VERSION 5.7 ;
BUSBITCHARS "[]" ;
DIVIDERCHAR "/" ;

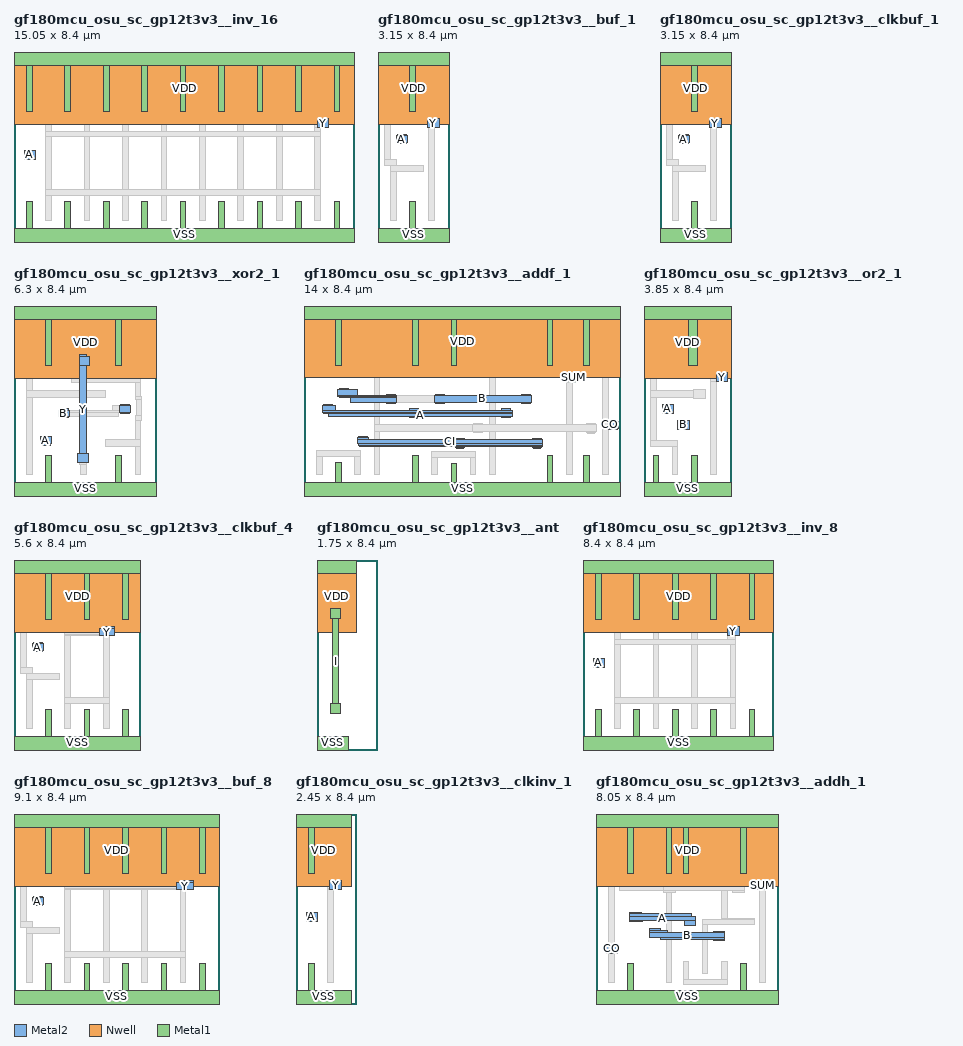
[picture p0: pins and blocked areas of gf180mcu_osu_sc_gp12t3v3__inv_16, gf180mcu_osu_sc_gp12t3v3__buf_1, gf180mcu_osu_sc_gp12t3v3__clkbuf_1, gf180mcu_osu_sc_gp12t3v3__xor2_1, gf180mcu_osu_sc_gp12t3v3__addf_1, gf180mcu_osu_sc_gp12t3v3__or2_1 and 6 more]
MACRO gf180mcu_osu_sc_gp12t3v3__inv_16
  CLASS BLOCK ;
  ORIGIN 0 0 ;
  FOREIGN gf180mcu_osu_sc_gp12t3v3__inv_16 ;
  SIZE 15.050 BY 8.400 ;
  PIN A
    ANTENNAGATEAREA 12.240001 ;
    PORT
      LAYER Metal2 ;
        RECT 0.450 3.650 0.950 4.050 ;
    END
  END A
  PIN Y
    ANTENNADIFFAREA 11.220001 ;
    PORT
      LAYER Metal2 ;
        RECT 13.400 5.050 13.900 5.450 ;
    END
  END Y
  PIN VDD
    ANTENNADIFFAREA 12.295001 ;
    PORT
      LAYER Nwell ;
        RECT 0.000 5.200 15.050 8.400 ;
      LAYER Metal1 ;
        RECT 0.000 7.800 15.050 8.400 ;
        RECT 0.550 5.750 0.800 7.800 ;
        RECT 2.250 5.750 2.500 7.800 ;
        RECT 3.950 5.750 4.200 7.800 ;
        RECT 5.650 5.750 5.900 7.800 ;
        RECT 7.350 5.750 7.600 7.800 ;
        RECT 9.050 5.750 9.300 7.800 ;
        RECT 10.750 5.750 11.000 7.800 ;
        RECT 12.450 5.750 12.700 7.800 ;
        RECT 14.150 5.750 14.400 7.800 ;
    END
  END VDD
  PIN VSS
    ANTENNADIFFAREA 8.172501 ;
    PORT
      LAYER Metal1 ;
        RECT 0.550 0.600 0.800 1.800 ;
        RECT 2.250 0.600 2.500 1.800 ;
        RECT 3.950 0.600 4.200 1.800 ;
        RECT 5.650 0.600 5.900 1.800 ;
        RECT 7.350 0.600 7.600 1.800 ;
        RECT 9.050 0.600 9.300 1.800 ;
        RECT 10.750 0.600 11.000 1.800 ;
        RECT 12.450 0.600 12.700 1.800 ;
        RECT 14.150 0.600 14.400 1.800 ;
        RECT 0.000 0.000 15.050 0.600 ;
    END
  END VSS
  OBS
      LAYER Metal1 ;
        RECT 1.400 4.900 1.650 7.450 ;
        RECT 3.100 4.900 3.350 7.450 ;
        RECT 4.800 4.900 5.050 7.450 ;
        RECT 6.500 4.900 6.750 7.450 ;
        RECT 8.200 4.900 8.450 7.450 ;
        RECT 9.900 4.900 10.150 7.450 ;
        RECT 11.600 4.900 11.850 7.450 ;
        RECT 13.300 5.500 13.550 7.450 ;
        RECT 13.300 5.050 13.900 5.500 ;
        RECT 13.300 4.900 13.550 5.050 ;
        RECT 1.400 4.650 13.550 4.900 ;
        RECT 0.450 3.700 0.950 4.000 ;
        RECT 1.400 2.300 1.650 4.650 ;
        RECT 3.100 2.300 3.350 4.650 ;
        RECT 4.800 2.300 5.050 4.650 ;
        RECT 6.500 2.300 6.750 4.650 ;
        RECT 8.200 2.300 8.450 4.650 ;
        RECT 9.900 2.300 10.150 4.650 ;
        RECT 11.600 2.300 11.850 4.650 ;
        RECT 13.300 2.300 13.550 4.650 ;
        RECT 1.400 2.050 13.550 2.300 ;
        RECT 1.400 0.950 1.650 2.050 ;
        RECT 3.100 0.950 3.350 2.050 ;
        RECT 4.800 0.950 5.050 2.050 ;
        RECT 6.500 0.950 6.750 2.050 ;
        RECT 8.200 0.950 8.450 2.050 ;
        RECT 9.900 0.950 10.150 2.050 ;
        RECT 11.600 0.950 11.850 2.050 ;
        RECT 13.300 0.950 13.550 2.050 ;
      LAYER Via1 ;
        RECT 13.500 5.100 13.800 5.400 ;
        RECT 0.550 3.700 0.850 4.000 ;
  END
END gf180mcu_osu_sc_gp12t3v3__inv_16


MACRO gf180mcu_osu_sc_gp12t3v3__buf_1
  CLASS BLOCK ;
  ORIGIN 0 0 ;
  FOREIGN gf180mcu_osu_sc_gp12t3v3__buf_1 ;
  SIZE 3.150 BY 8.400 ;
  PIN A
    ANTENNAGATEAREA 0.765000 ;
    PORT
      LAYER Metal2 ;
        RECT 0.850 4.700 1.250 4.750 ;
        RECT 0.800 4.400 1.300 4.700 ;
        RECT 0.850 4.350 1.250 4.400 ;
    END
  END A
  PIN Y
    ANTENNADIFFAREA 1.275000 ;
    PORT
      LAYER Metal2 ;
        RECT 2.200 5.050 2.700 5.450 ;
    END
  END Y
  PIN VDD
    ANTENNADIFFAREA 1.610000 ;
    PORT
      LAYER Nwell ;
        RECT 0.000 5.200 3.150 8.400 ;
      LAYER Metal1 ;
        RECT 0.000 7.800 3.150 8.400 ;
        RECT 1.400 5.750 1.650 7.800 ;
    END
  END VDD
  PIN VSS
    ANTENNADIFFAREA 1.142500 ;
    PORT
      LAYER Metal1 ;
        RECT 1.400 0.600 1.650 1.800 ;
        RECT 0.000 0.000 3.150 0.600 ;
    END
  END VSS
  OBS
      LAYER Metal1 ;
        RECT 0.550 5.750 0.800 7.450 ;
        RECT 0.300 5.500 0.800 5.750 ;
        RECT 0.300 3.650 0.550 5.500 ;
        RECT 2.250 5.450 2.500 7.450 ;
        RECT 2.250 5.400 2.550 5.450 ;
        RECT 2.200 5.100 2.700 5.400 ;
        RECT 2.250 5.050 2.550 5.100 ;
        RECT 0.800 4.400 1.300 4.700 ;
        RECT 0.300 3.400 0.800 3.650 ;
        RECT 0.550 3.100 2.000 3.400 ;
        RECT 0.550 0.950 0.800 3.100 ;
        RECT 2.250 0.950 2.500 5.050 ;
      LAYER Via1 ;
        RECT 2.300 5.100 2.600 5.400 ;
        RECT 0.900 4.400 1.200 4.700 ;
  END
END gf180mcu_osu_sc_gp12t3v3__buf_1


MACRO gf180mcu_osu_sc_gp12t3v3__clkbuf_1
  CLASS BLOCK ;
  ORIGIN 0 0 ;
  FOREIGN gf180mcu_osu_sc_gp12t3v3__clkbuf_1 ;
  SIZE 3.150 BY 8.400 ;
  PIN A
    ANTENNAGATEAREA 0.765000 ;
    PORT
      LAYER Metal2 ;
        RECT 0.850 4.700 1.250 4.750 ;
        RECT 0.800 4.400 1.300 4.700 ;
        RECT 0.850 4.350 1.250 4.400 ;
    END
  END A
  PIN Y
    ANTENNADIFFAREA 1.275000 ;
    PORT
      LAYER Metal2 ;
        RECT 2.200 5.050 2.700 5.450 ;
    END
  END Y
  PIN VDD
    ANTENNADIFFAREA 1.610000 ;
    PORT
      LAYER Nwell ;
        RECT 0.000 5.200 3.150 8.400 ;
      LAYER Metal1 ;
        RECT 0.000 7.800 3.150 8.400 ;
        RECT 1.400 5.750 1.650 7.800 ;
    END
  END VDD
  PIN VSS
    ANTENNADIFFAREA 1.142500 ;
    PORT
      LAYER Metal1 ;
        RECT 1.400 0.600 1.650 1.800 ;
        RECT 0.000 0.000 3.150 0.600 ;
    END
  END VSS
  OBS
      LAYER Metal1 ;
        RECT 0.550 6.100 0.800 7.450 ;
        RECT 0.300 5.750 0.800 6.100 ;
        RECT 0.300 3.650 0.550 5.750 ;
        RECT 2.250 5.450 2.500 7.450 ;
        RECT 2.250 5.400 2.550 5.450 ;
        RECT 2.200 5.100 2.700 5.400 ;
        RECT 2.250 5.050 2.550 5.100 ;
        RECT 0.800 4.400 1.300 4.700 ;
        RECT 0.300 3.400 0.800 3.650 ;
        RECT 0.550 3.100 2.000 3.400 ;
        RECT 0.550 0.950 0.800 3.100 ;
        RECT 2.250 0.950 2.500 5.050 ;
      LAYER Via1 ;
        RECT 2.300 5.100 2.600 5.400 ;
        RECT 0.900 4.400 1.200 4.700 ;
  END
END gf180mcu_osu_sc_gp12t3v3__clkbuf_1


MACRO gf180mcu_osu_sc_gp12t3v3__xor2_1
  CLASS BLOCK ;
  ORIGIN 0 0 ;
  FOREIGN gf180mcu_osu_sc_gp12t3v3__xor2_1 ;
  SIZE 6.300 BY 8.400 ;
  PIN A
    ANTENNAGATEAREA 1.530000 ;
    PORT
      LAYER Metal2 ;
        RECT 1.150 2.300 1.650 2.650 ;
        RECT 1.200 2.250 1.600 2.300 ;
    END
  END A
  PIN B
    ANTENNAGATEAREA 1.530000 ;
    PORT
      LAYER Metal2 ;
        RECT 4.700 4.000 5.100 4.050 ;
        RECT 2.000 3.800 2.400 3.850 ;
        RECT 1.950 3.500 2.450 3.800 ;
        RECT 4.650 3.700 5.150 4.000 ;
        RECT 4.700 3.650 5.100 3.700 ;
        RECT 2.000 3.450 2.400 3.500 ;
    END
  END B
  PIN Y
    ANTENNADIFFAREA 2.192500 ;
    PORT
      LAYER Metal2 ;
        RECT 2.900 6.150 3.200 6.250 ;
        RECT 2.900 5.750 3.350 6.150 ;
        RECT 2.900 1.900 3.200 5.750 ;
        RECT 2.800 1.500 3.300 1.900 ;
    END
  END Y
  PIN VDD
    ANTENNADIFFAREA 3.557500 ;
    PORT
      LAYER Nwell ;
        RECT 0.000 5.200 6.300 8.400 ;
      LAYER Metal1 ;
        RECT 0.000 7.800 6.300 8.400 ;
        RECT 1.400 5.750 1.650 7.800 ;
        RECT 4.500 5.750 4.750 7.800 ;
    END
  END VDD
  PIN VSS
    ANTENNADIFFAREA 2.622500 ;
    PORT
      LAYER Metal1 ;
        RECT 1.400 0.600 1.650 1.800 ;
        RECT 4.500 0.600 4.750 1.800 ;
        RECT 0.000 0.000 6.300 0.600 ;
    END
  END VSS
  OBS
      LAYER Metal1 ;
        RECT 0.550 4.650 0.800 7.450 ;
        RECT 2.950 6.250 3.200 7.450 ;
        RECT 2.900 6.150 3.200 6.250 ;
        RECT 2.900 5.750 3.350 6.150 ;
        RECT 2.900 5.650 3.200 5.750 ;
        RECT 5.350 5.300 5.600 7.450 ;
        RECT 2.550 5.000 5.600 5.300 ;
        RECT 0.550 4.350 4.050 4.650 ;
        RECT 5.350 4.400 5.600 5.000 ;
        RECT 0.550 0.950 0.800 4.350 ;
        RECT 5.350 4.250 5.650 4.400 ;
        RECT 4.350 3.800 5.150 4.000 ;
        RECT 1.950 3.700 5.150 3.800 ;
        RECT 1.950 3.500 4.600 3.700 ;
        RECT 5.400 3.550 5.650 4.250 ;
        RECT 5.350 3.350 5.650 3.550 ;
        RECT 1.150 2.300 1.650 2.650 ;
        RECT 5.350 2.500 5.600 3.350 ;
        RECT 4.050 2.200 5.600 2.500 ;
        RECT 2.900 1.400 3.200 1.950 ;
        RECT 2.950 0.950 3.200 1.400 ;
        RECT 5.350 0.950 5.600 2.200 ;
      LAYER Via1 ;
        RECT 3.000 5.800 3.300 6.100 ;
        RECT 2.050 3.500 2.350 3.800 ;
        RECT 4.750 3.700 5.050 4.000 ;
        RECT 1.250 2.300 1.550 2.600 ;
        RECT 2.900 1.550 3.200 1.850 ;
  END
END gf180mcu_osu_sc_gp12t3v3__xor2_1


MACRO gf180mcu_osu_sc_gp12t3v3__addf_1
  CLASS BLOCK ;
  ORIGIN 0 0 ;
  FOREIGN gf180mcu_osu_sc_gp12t3v3__addf_1 ;
  SIZE 14.000 BY 8.400 ;
  PIN A
    ANTENNAGATEAREA 3.060000 ;
    PORT
      LAYER Metal2 ;
        RECT 0.850 4.000 1.250 4.050 ;
        RECT 0.800 3.800 1.400 4.000 ;
        RECT 4.650 3.800 5.050 3.850 ;
        RECT 8.750 3.800 9.150 3.850 ;
        RECT 0.800 3.700 9.200 3.800 ;
        RECT 0.850 3.650 9.200 3.700 ;
        RECT 1.100 3.500 9.200 3.650 ;
        RECT 4.650 3.450 5.050 3.500 ;
        RECT 8.750 3.450 9.150 3.500 ;
    END
  END A
  PIN B
    ANTENNAGATEAREA 3.060000 ;
    PORT
      LAYER Metal2 ;
        RECT 1.550 4.700 1.950 4.750 ;
        RECT 1.500 4.450 2.350 4.700 ;
        RECT 3.650 4.450 4.050 4.500 ;
        RECT 5.800 4.450 6.200 4.500 ;
        RECT 9.600 4.450 10.000 4.500 ;
        RECT 1.500 4.400 4.100 4.450 ;
        RECT 1.550 4.350 4.100 4.400 ;
        RECT 2.050 4.150 4.100 4.350 ;
        RECT 5.750 4.150 10.050 4.450 ;
        RECT 3.650 4.100 4.050 4.150 ;
        RECT 5.800 4.100 6.200 4.150 ;
        RECT 9.600 4.100 10.000 4.150 ;
    END
  END B
  PIN CI
    ANTENNAGATEAREA 2.295000 ;
    PORT
      LAYER Metal2 ;
        RECT 2.400 2.600 2.800 2.650 ;
        RECT 2.350 2.500 2.850 2.600 ;
        RECT 6.700 2.500 7.100 2.550 ;
        RECT 10.100 2.500 10.500 2.550 ;
        RECT 2.350 2.300 10.550 2.500 ;
        RECT 2.400 2.250 10.550 2.300 ;
        RECT 2.450 2.200 10.550 2.250 ;
        RECT 6.700 2.150 7.100 2.200 ;
        RECT 10.100 2.150 10.500 2.200 ;
        RECT 6.750 2.100 7.050 2.150 ;
        RECT 10.150 2.100 10.450 2.150 ;
    END
  END CI
  PIN SUM
    ANTENNADIFFAREA 1.275000 ;
    PORT
      LAYER Metal2 ;
        RECT 11.700 5.400 12.100 5.450 ;
        RECT 11.650 5.100 12.150 5.400 ;
        RECT 11.700 5.050 12.100 5.100 ;
    END
  END SUM
  PIN CO
    ANTENNADIFFAREA 1.275000 ;
    PORT
      LAYER Metal2 ;
        RECT 13.450 3.300 13.850 3.350 ;
        RECT 13.400 3.000 13.900 3.300 ;
        RECT 13.450 2.950 13.850 3.000 ;
    END
  END CO
  PIN VSS
    ANTENNADIFFAREA 6.007501 ;
    PORT
      LAYER Metal1 ;
        RECT 1.400 0.600 1.650 1.500 ;
        RECT 4.800 0.600 5.050 1.800 ;
        RECT 6.500 0.600 6.750 1.450 ;
        RECT 10.750 0.600 11.000 1.800 ;
        RECT 12.350 0.600 12.600 1.800 ;
        RECT 0.000 0.000 14.000 0.600 ;
    END
  END VSS
  PIN VDD
    ANTENNADIFFAREA 8.302501 ;
    PORT
      LAYER Nwell ;
        RECT 0.000 5.250 14.000 8.400 ;
      LAYER Metal1 ;
        RECT 0.000 7.800 14.000 8.400 ;
        RECT 1.400 5.750 1.650 7.800 ;
        RECT 4.800 5.750 5.050 7.800 ;
        RECT 6.500 5.750 6.750 7.800 ;
        RECT 10.750 5.750 11.000 7.800 ;
        RECT 12.350 5.750 12.600 7.800 ;
    END
  END VDD
  OBS
      LAYER Metal1 ;
        RECT 0.550 5.500 0.800 7.450 ;
        RECT 2.250 5.500 2.500 7.450 ;
        RECT 0.550 5.250 2.500 5.500 ;
        RECT 1.500 4.400 2.000 4.700 ;
        RECT 0.800 3.700 1.300 4.000 ;
        RECT 3.100 3.150 3.350 7.450 ;
        RECT 5.650 5.500 5.900 7.450 ;
        RECT 7.350 5.500 7.600 7.450 ;
        RECT 5.650 5.250 7.600 5.500 ;
        RECT 3.600 4.150 6.250 4.450 ;
        RECT 4.600 3.500 5.100 3.800 ;
        RECT 8.200 3.150 8.450 7.450 ;
        RECT 11.600 5.450 11.850 7.450 ;
        RECT 11.600 5.400 12.000 5.450 ;
        RECT 11.600 5.100 12.150 5.400 ;
        RECT 11.600 5.000 12.000 5.100 ;
        RECT 9.550 4.150 10.050 4.450 ;
        RECT 8.700 3.500 9.200 3.800 ;
        RECT 3.100 2.850 7.950 3.150 ;
        RECT 8.200 2.850 11.350 3.150 ;
        RECT 2.350 2.300 2.850 2.600 ;
        RECT 0.550 1.750 2.500 2.000 ;
        RECT 0.550 0.950 0.800 1.750 ;
        RECT 2.250 0.950 2.500 1.750 ;
        RECT 3.100 0.950 3.350 2.850 ;
        RECT 6.650 2.200 7.150 2.500 ;
        RECT 5.650 1.700 7.600 1.950 ;
        RECT 5.650 0.950 5.900 1.700 ;
        RECT 7.350 0.950 7.600 1.700 ;
        RECT 8.200 0.950 8.450 2.850 ;
        RECT 10.050 2.200 10.550 2.500 ;
        RECT 11.600 0.950 11.850 5.000 ;
        RECT 13.200 3.350 13.450 7.450 ;
        RECT 13.200 3.300 13.750 3.350 ;
        RECT 12.450 2.850 12.950 3.150 ;
        RECT 13.200 3.000 13.900 3.300 ;
        RECT 13.200 2.950 13.750 3.000 ;
        RECT 13.200 0.950 13.450 2.950 ;
      LAYER Via1 ;
        RECT 1.600 4.400 1.900 4.700 ;
        RECT 0.900 3.700 1.200 4.000 ;
        RECT 3.700 4.150 4.000 4.450 ;
        RECT 5.850 4.150 6.150 4.450 ;
        RECT 4.700 3.500 5.000 3.800 ;
        RECT 11.750 5.100 12.050 5.400 ;
        RECT 9.650 4.150 9.950 4.450 ;
        RECT 8.800 3.500 9.100 3.800 ;
        RECT 7.550 2.850 7.850 3.150 ;
        RECT 2.450 2.300 2.750 2.600 ;
        RECT 6.750 2.200 7.050 2.500 ;
        RECT 10.150 2.200 10.450 2.500 ;
        RECT 12.550 2.850 12.850 3.150 ;
        RECT 13.500 3.000 13.800 3.300 ;
      LAYER Metal2 ;
        RECT 7.500 3.150 7.900 3.200 ;
        RECT 12.500 3.150 12.900 3.200 ;
        RECT 7.450 2.850 12.950 3.150 ;
        RECT 7.500 2.800 7.900 2.850 ;
        RECT 12.500 2.800 12.900 2.850 ;
        RECT 12.550 2.750 12.850 2.800 ;
  END
END gf180mcu_osu_sc_gp12t3v3__addf_1


MACRO gf180mcu_osu_sc_gp12t3v3__or2_1
  CLASS BLOCK ;
  ORIGIN 0 0 ;
  FOREIGN gf180mcu_osu_sc_gp12t3v3__or2_1 ;
  SIZE 3.850 BY 8.400 ;
  PIN A
    ANTENNAGATEAREA 0.765000 ;
    PORT
      LAYER Metal2 ;
        RECT 0.800 3.650 1.300 4.050 ;
    END
  END A
  PIN B
    ANTENNAGATEAREA 0.765000 ;
    PORT
      LAYER Metal2 ;
        RECT 1.500 2.950 2.000 3.350 ;
    END
  END B
  PIN Y
    ANTENNADIFFAREA 1.275000 ;
    PORT
      LAYER Metal2 ;
        RECT 3.200 5.050 3.700 5.450 ;
    END
  END Y
  PIN VDD
    ANTENNADIFFAREA 2.202500 ;
    PORT
      LAYER Nwell ;
        RECT 0.000 5.200 3.850 8.400 ;
      LAYER Metal1 ;
        RECT 0.000 7.800 3.850 8.400 ;
        RECT 1.950 5.750 2.350 7.800 ;
    END
  END VDD
  PIN VSS
    ANTENNADIFFAREA 1.905000 ;
    PORT
      LAYER Metal1 ;
        RECT 0.400 0.600 0.650 1.800 ;
        RECT 2.100 0.600 2.350 1.800 ;
        RECT 0.000 0.000 3.850 0.600 ;
    END
  END VSS
  OBS
      LAYER Metal1 ;
        RECT 0.550 5.800 0.800 7.450 ;
        RECT 0.300 5.500 0.800 5.800 ;
        RECT 0.300 4.650 0.550 5.500 ;
        RECT 2.950 5.450 3.200 7.450 ;
        RECT 2.950 5.050 3.700 5.450 ;
        RECT 0.300 4.350 2.700 4.650 ;
        RECT 0.300 2.450 0.550 4.350 ;
        RECT 0.800 3.700 1.300 4.000 ;
        RECT 1.500 3.000 2.000 3.300 ;
        RECT 0.300 2.200 1.500 2.450 ;
        RECT 1.250 0.950 1.500 2.200 ;
        RECT 2.950 0.950 3.200 5.050 ;
      LAYER Via1 ;
        RECT 3.300 5.100 3.600 5.400 ;
        RECT 2.300 4.350 2.600 4.650 ;
        RECT 0.900 3.700 1.200 4.000 ;
        RECT 1.600 3.000 1.900 3.300 ;
      LAYER Metal2 ;
        RECT 2.200 4.300 2.700 4.700 ;
  END
END gf180mcu_osu_sc_gp12t3v3__or2_1


MACRO gf180mcu_osu_sc_gp12t3v3__clkbuf_4
  CLASS BLOCK ;
  ORIGIN 0 0 ;
  FOREIGN gf180mcu_osu_sc_gp12t3v3__clkbuf_4 ;
  SIZE 5.600 BY 8.400 ;
  PIN A
    ANTENNAGATEAREA 0.765000 ;
    PORT
      LAYER Metal2 ;
        RECT 0.850 4.700 1.250 4.750 ;
        RECT 0.800 4.400 1.300 4.700 ;
        RECT 0.850 4.350 1.250 4.400 ;
    END
  END A
  PIN Y
    ANTENNADIFFAREA 2.805000 ;
    PORT
      LAYER Metal2 ;
        RECT 3.900 5.350 4.450 5.450 ;
        RECT 3.800 5.050 4.450 5.350 ;
    END
  END Y
  PIN VDD
    ANTENNADIFFAREA 4.070000 ;
    PORT
      LAYER Nwell ;
        RECT 0.000 5.200 5.600 8.400 ;
      LAYER Metal1 ;
        RECT 0.000 7.800 5.600 8.400 ;
        RECT 1.400 5.750 1.650 7.800 ;
        RECT 3.100 5.750 3.350 7.800 ;
        RECT 4.800 5.750 5.050 7.800 ;
    END
  END VDD
  PIN VSS
    ANTENNADIFFAREA 2.710000 ;
    PORT
      LAYER Metal1 ;
        RECT 1.400 0.600 1.650 1.800 ;
        RECT 3.100 0.600 3.350 1.800 ;
        RECT 4.800 0.600 5.050 1.800 ;
        RECT 0.000 0.000 5.600 0.600 ;
    END
  END VSS
  OBS
      LAYER Metal1 ;
        RECT 0.550 6.100 0.800 7.450 ;
        RECT 0.300 5.750 0.800 6.100 ;
        RECT 0.300 3.650 0.550 5.750 ;
        RECT 2.250 5.350 2.500 7.450 ;
        RECT 3.950 5.450 4.200 7.450 ;
        RECT 3.950 5.400 4.300 5.450 ;
        RECT 3.900 5.350 4.450 5.400 ;
        RECT 2.250 5.100 4.450 5.350 ;
        RECT 2.250 5.050 4.300 5.100 ;
        RECT 0.800 4.400 1.300 4.700 ;
        RECT 0.300 3.400 0.800 3.650 ;
        RECT 0.550 3.100 2.000 3.400 ;
        RECT 0.550 0.950 0.800 3.100 ;
        RECT 2.250 2.300 2.500 5.050 ;
        RECT 3.950 2.300 4.200 5.050 ;
        RECT 2.250 2.050 4.200 2.300 ;
        RECT 2.250 0.950 2.500 2.050 ;
        RECT 3.950 0.950 4.200 2.050 ;
      LAYER Via1 ;
        RECT 4.050 5.100 4.350 5.400 ;
        RECT 0.900 4.400 1.200 4.700 ;
  END
END gf180mcu_osu_sc_gp12t3v3__clkbuf_4


MACRO gf180mcu_osu_sc_gp12t3v3__ant
  CLASS BLOCK ;
  ORIGIN 0 0 ;
  FOREIGN gf180mcu_osu_sc_gp12t3v3__ant ;
  SIZE 1.750 BY 8.400 ;
  PIN VDD
    ANTENNADIFFAREA 0.337500 ;
    PORT
      LAYER Nwell ;
        RECT 0.000 5.200 1.750 8.400 ;
      LAYER Metal1 ;
        RECT 0.000 7.800 1.750 8.400 ;
    END
  END VDD
  PIN VSS
    ANTENNADIFFAREA 0.337500 ;
    PORT
      LAYER Metal1 ;
        RECT 0.000 0.000 1.400 0.600 ;
    END
  END VSS
  PIN I
    ANTENNADIFFAREA 0.585000 ;
    PORT
      LAYER Metal1 ;
        RECT 0.600 5.800 1.050 6.250 ;
        RECT 0.700 2.050 0.950 5.800 ;
        RECT 0.600 1.600 1.050 2.050 ;
    END
  END I
END gf180mcu_osu_sc_gp12t3v3__ant


MACRO gf180mcu_osu_sc_gp12t3v3__inv_8
  CLASS BLOCK ;
  ORIGIN 0 0 ;
  FOREIGN gf180mcu_osu_sc_gp12t3v3__inv_8 ;
  SIZE 8.400 BY 8.400 ;
  PIN A
    ANTENNAGATEAREA 6.120000 ;
    PORT
      LAYER Metal2 ;
        RECT 0.450 3.650 0.950 4.050 ;
    END
  END A
  PIN Y
    ANTENNADIFFAREA 5.610001 ;
    PORT
      LAYER Metal2 ;
        RECT 6.400 5.050 6.900 5.450 ;
    END
  END Y
  PIN VDD
    ANTENNADIFFAREA 6.530001 ;
    PORT
      LAYER Nwell ;
        RECT 0.000 5.200 8.400 8.400 ;
      LAYER Metal1 ;
        RECT 0.000 7.800 8.400 8.400 ;
        RECT 0.550 5.750 0.800 7.800 ;
        RECT 2.250 5.750 2.500 7.800 ;
        RECT 3.950 5.750 4.200 7.800 ;
        RECT 5.650 5.750 5.900 7.800 ;
        RECT 7.350 5.750 7.600 7.800 ;
    END
  END VDD
  PIN VSS
    ANTENNADIFFAREA 4.277500 ;
    PORT
      LAYER Metal1 ;
        RECT 0.550 0.600 0.800 1.800 ;
        RECT 2.250 0.600 2.500 1.800 ;
        RECT 3.950 0.600 4.200 1.800 ;
        RECT 5.650 0.600 5.900 1.800 ;
        RECT 7.350 0.600 7.600 1.800 ;
        RECT 0.000 0.000 8.400 0.600 ;
    END
  END VSS
  OBS
      LAYER Metal1 ;
        RECT 1.400 4.900 1.650 7.450 ;
        RECT 3.100 4.900 3.350 7.450 ;
        RECT 4.800 4.900 5.050 7.450 ;
        RECT 6.500 5.450 6.750 7.450 ;
        RECT 6.400 5.050 6.900 5.450 ;
        RECT 6.400 4.900 6.750 5.050 ;
        RECT 1.400 4.650 6.750 4.900 ;
        RECT 0.450 3.700 0.950 4.000 ;
        RECT 1.400 2.300 1.650 4.650 ;
        RECT 3.100 2.300 3.350 4.650 ;
        RECT 4.800 2.300 5.050 4.650 ;
        RECT 6.500 2.300 6.750 4.650 ;
        RECT 1.400 2.050 6.750 2.300 ;
        RECT 1.400 0.950 1.650 2.050 ;
        RECT 3.100 0.950 3.350 2.050 ;
        RECT 4.800 0.950 5.050 2.050 ;
        RECT 6.500 0.950 6.750 2.050 ;
      LAYER Via1 ;
        RECT 6.500 5.100 6.800 5.400 ;
        RECT 0.550 3.700 0.850 4.000 ;
  END
END gf180mcu_osu_sc_gp12t3v3__inv_8


MACRO gf180mcu_osu_sc_gp12t3v3__buf_8
  CLASS BLOCK ;
  ORIGIN 0 0 ;
  FOREIGN gf180mcu_osu_sc_gp12t3v3__buf_8 ;
  SIZE 9.100 BY 8.400 ;
  PIN A
    ANTENNAGATEAREA 0.765000 ;
    PORT
      LAYER Metal2 ;
        RECT 0.850 4.700 1.250 4.750 ;
        RECT 0.800 4.400 1.300 4.700 ;
        RECT 0.850 4.350 1.250 4.400 ;
    END
  END A
  PIN Y
    ANTENNADIFFAREA 5.610001 ;
    PORT
      LAYER Metal2 ;
        RECT 7.450 5.350 7.950 5.450 ;
        RECT 7.200 5.050 7.950 5.350 ;
    END
  END Y
  PIN VDD
    ANTENNADIFFAREA 6.615000 ;
    PORT
      LAYER Nwell ;
        RECT 0.000 5.200 9.100 8.400 ;
      LAYER Metal1 ;
        RECT 0.000 7.800 9.100 8.400 ;
        RECT 1.400 5.750 1.650 7.800 ;
        RECT 3.100 5.750 3.350 7.800 ;
        RECT 4.800 5.750 5.050 7.800 ;
        RECT 6.500 5.750 6.750 7.800 ;
        RECT 8.200 5.750 8.450 7.800 ;
    END
  END VDD
  PIN VSS
    ANTENNADIFFAREA 4.320000 ;
    PORT
      LAYER Metal1 ;
        RECT 1.400 0.600 1.650 1.800 ;
        RECT 3.100 0.600 3.350 1.800 ;
        RECT 4.800 0.600 5.050 1.800 ;
        RECT 6.500 0.600 6.750 1.800 ;
        RECT 8.200 0.600 8.450 1.800 ;
        RECT 0.000 0.000 9.100 0.600 ;
    END
  END VSS
  OBS
      LAYER Metal1 ;
        RECT 0.550 6.100 0.800 7.450 ;
        RECT 0.300 5.750 0.800 6.100 ;
        RECT 0.300 3.650 0.550 5.750 ;
        RECT 2.250 5.350 2.500 7.450 ;
        RECT 3.950 5.350 4.200 7.450 ;
        RECT 5.650 5.350 5.900 7.450 ;
        RECT 7.350 5.450 7.600 7.450 ;
        RECT 7.350 5.400 7.800 5.450 ;
        RECT 7.350 5.350 7.950 5.400 ;
        RECT 2.250 5.100 7.950 5.350 ;
        RECT 2.250 5.050 7.800 5.100 ;
        RECT 0.800 4.400 1.300 4.700 ;
        RECT 0.300 3.400 0.800 3.650 ;
        RECT 0.550 3.100 2.000 3.400 ;
        RECT 0.550 0.950 0.800 3.100 ;
        RECT 2.250 2.300 2.500 5.050 ;
        RECT 3.950 2.300 4.200 5.050 ;
        RECT 5.650 2.300 5.900 5.050 ;
        RECT 7.350 2.300 7.600 5.050 ;
        RECT 2.250 2.050 7.600 2.300 ;
        RECT 2.250 0.950 2.500 2.050 ;
        RECT 3.950 0.950 4.200 2.050 ;
        RECT 5.650 0.950 5.900 2.050 ;
        RECT 7.350 0.950 7.600 2.050 ;
      LAYER Via1 ;
        RECT 7.550 5.100 7.850 5.400 ;
        RECT 0.900 4.400 1.200 4.700 ;
  END
END gf180mcu_osu_sc_gp12t3v3__buf_8


MACRO gf180mcu_osu_sc_gp12t3v3__clkinv_1
  CLASS BLOCK ;
  ORIGIN 0 0 ;
  FOREIGN gf180mcu_osu_sc_gp12t3v3__clkinv_1 ;
  SIZE 2.450 BY 8.400 ;
  PIN A
    ANTENNAGATEAREA 0.765000 ;
    PORT
      LAYER Metal2 ;
        RECT 0.450 3.650 0.950 4.050 ;
    END
  END A
  PIN Y
    ANTENNADIFFAREA 1.275000 ;
    PORT
      LAYER Metal2 ;
        RECT 1.500 5.050 2.000 5.450 ;
    END
  END Y
  PIN VDD
    ANTENNADIFFAREA 1.187500 ;
    PORT
      LAYER Nwell ;
        RECT 0.000 5.200 2.450 8.400 ;
      LAYER Metal1 ;
        RECT 0.000 7.800 2.450 8.400 ;
        RECT 0.550 5.750 0.800 7.800 ;
    END
  END VDD
  PIN VSS
    ANTENNADIFFAREA 0.762500 ;
    PORT
      LAYER Metal1 ;
        RECT 0.550 0.600 0.800 1.800 ;
        RECT 0.000 0.000 2.450 0.600 ;
    END
  END VSS
  OBS
      LAYER Metal1 ;
        RECT 1.400 5.450 1.650 7.450 ;
        RECT 1.400 5.400 1.850 5.450 ;
        RECT 1.400 5.100 2.000 5.400 ;
        RECT 1.400 5.050 1.850 5.100 ;
        RECT 0.450 3.700 0.950 4.000 ;
        RECT 1.400 0.950 1.650 5.050 ;
      LAYER Via1 ;
        RECT 1.600 5.100 1.900 5.400 ;
        RECT 0.550 3.700 0.850 4.000 ;
  END
END gf180mcu_osu_sc_gp12t3v3__clkinv_1


MACRO gf180mcu_osu_sc_gp12t3v3__addh_1
  CLASS BLOCK ;
  ORIGIN 0 0 ;
  FOREIGN gf180mcu_osu_sc_gp12t3v3__addh_1 ;
  SIZE 8.050 BY 8.400 ;
  PIN A
    ANTENNAGATEAREA 1.530000 ;
    PORT
      LAYER Metal2 ;
        RECT 1.500 4.000 2.000 4.050 ;
        RECT 1.500 3.850 4.200 4.000 ;
        RECT 1.500 3.700 4.400 3.850 ;
        RECT 1.500 3.650 2.050 3.700 ;
        RECT 3.900 3.450 4.400 3.700 ;
    END
  END A
  PIN B
    ANTENNAGATEAREA 1.530000 ;
    PORT
      LAYER Metal2 ;
        RECT 2.350 3.250 2.850 3.350 ;
        RECT 2.350 3.150 3.150 3.250 ;
        RECT 5.200 3.150 5.700 3.200 ;
        RECT 2.350 2.950 5.700 3.150 ;
        RECT 2.850 2.850 5.700 2.950 ;
        RECT 5.200 2.800 5.700 2.850 ;
    END
  END B
  PIN SUM
    ANTENNADIFFAREA 1.275000 ;
    PORT
      LAYER Metal2 ;
        RECT 7.100 5.050 7.600 5.450 ;
    END
  END SUM
  PIN CO
    ANTENNADIFFAREA 1.275000 ;
    PORT
      LAYER Metal2 ;
        RECT 0.450 2.250 0.950 2.650 ;
    END
  END CO
  PIN VDD
    ANTENNADIFFAREA 5.595000 ;
    PORT
      LAYER Nwell ;
        RECT 0.000 5.200 8.050 8.400 ;
      LAYER Metal1 ;
        RECT 0.000 7.800 8.050 8.400 ;
        RECT 1.400 5.750 1.650 7.800 ;
        RECT 3.100 5.750 3.350 7.800 ;
        RECT 3.850 5.750 4.100 7.800 ;
        RECT 6.400 5.750 6.650 7.800 ;
    END
  END VDD
  PIN VSS
    ANTENNADIFFAREA 2.960000 ;
    PORT
      LAYER Metal1 ;
        RECT 1.400 0.600 1.650 1.800 ;
        RECT 6.400 0.600 6.650 1.800 ;
        RECT 0.000 0.000 8.050 0.600 ;
    END
  END VSS
  OBS
      LAYER Metal1 ;
        RECT 0.550 2.650 0.800 7.450 ;
        RECT 2.250 5.300 2.500 7.450 ;
        RECT 1.050 5.000 3.500 5.300 ;
        RECT 1.500 3.700 2.000 4.000 ;
        RECT 2.350 3.000 2.850 3.300 ;
        RECT 0.550 2.600 0.850 2.650 ;
        RECT 0.450 2.300 0.950 2.600 ;
        RECT 0.550 2.250 0.850 2.300 ;
        RECT 0.550 0.950 0.800 2.250 ;
        RECT 3.100 0.950 3.350 5.000 ;
        RECT 5.550 3.800 5.800 7.450 ;
        RECT 7.250 5.450 7.500 7.450 ;
        RECT 7.150 5.400 7.500 5.450 ;
        RECT 6.050 5.000 6.550 5.300 ;
        RECT 7.100 5.100 7.600 5.400 ;
        RECT 7.150 5.050 7.500 5.100 ;
        RECT 3.900 3.500 4.400 3.800 ;
        RECT 5.550 3.750 7.000 3.800 ;
        RECT 4.700 3.500 7.000 3.750 ;
        RECT 3.850 1.100 4.100 1.900 ;
        RECT 4.700 1.350 4.950 3.500 ;
        RECT 5.200 2.850 5.700 3.150 ;
        RECT 5.550 1.100 5.800 1.900 ;
        RECT 3.850 0.850 5.800 1.100 ;
        RECT 7.250 0.950 7.500 5.050 ;
      LAYER Via1 ;
        RECT 3.100 5.000 3.400 5.300 ;
        RECT 1.600 3.700 1.900 4.000 ;
        RECT 2.450 3.000 2.750 3.300 ;
        RECT 0.550 2.300 0.850 2.600 ;
        RECT 6.150 5.000 6.450 5.300 ;
        RECT 7.200 5.100 7.500 5.400 ;
        RECT 4.000 3.500 4.300 3.800 ;
        RECT 5.300 2.850 5.600 3.150 ;
      LAYER Metal2 ;
        RECT 3.000 5.300 3.500 5.350 ;
        RECT 6.050 5.300 6.550 5.350 ;
        RECT 3.000 5.000 6.550 5.300 ;
        RECT 3.000 4.950 3.500 5.000 ;
        RECT 6.050 4.950 6.550 5.000 ;
  END
END gf180mcu_osu_sc_gp12t3v3__addh_1


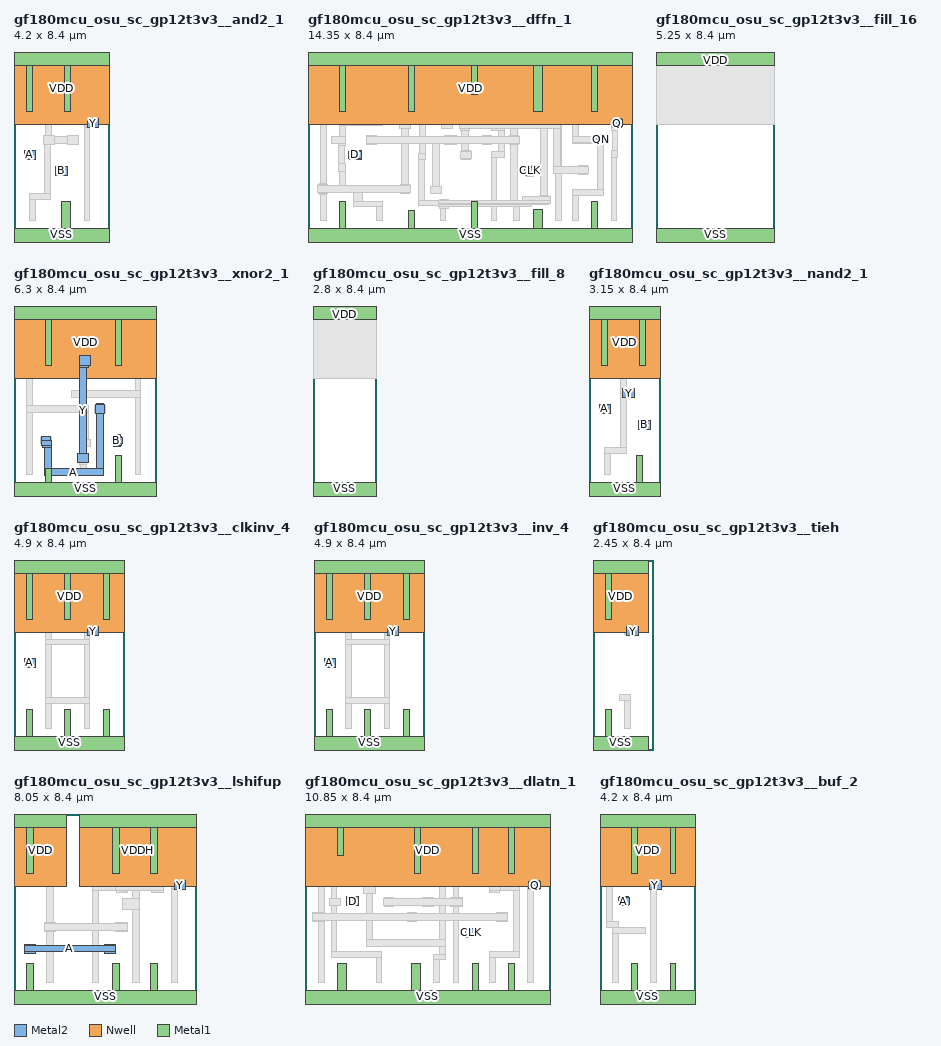
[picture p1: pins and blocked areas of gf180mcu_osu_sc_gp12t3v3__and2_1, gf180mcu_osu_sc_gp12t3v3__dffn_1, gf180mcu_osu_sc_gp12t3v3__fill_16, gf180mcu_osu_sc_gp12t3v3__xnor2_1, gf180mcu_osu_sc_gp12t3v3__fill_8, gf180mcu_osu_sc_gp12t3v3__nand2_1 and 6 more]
MACRO gf180mcu_osu_sc_gp12t3v3__and2_1
  CLASS BLOCK ;
  ORIGIN 0 0 ;
  FOREIGN gf180mcu_osu_sc_gp12t3v3__and2_1 ;
  SIZE 4.200 BY 8.400 ;
  PIN A
    ANTENNAGATEAREA 0.765000 ;
    PORT
      LAYER Metal2 ;
        RECT 0.450 3.650 0.950 4.050 ;
    END
  END A
  PIN B
    ANTENNAGATEAREA 0.765000 ;
    PORT
      LAYER Metal2 ;
        RECT 1.850 2.950 2.350 3.350 ;
    END
  END B
  PIN Y
    ANTENNADIFFAREA 1.275000 ;
    PORT
      LAYER Metal2 ;
        RECT 3.250 5.050 3.750 5.450 ;
    END
  END Y
  PIN VDD
    ANTENNADIFFAREA 2.797500 ;
    PORT
      LAYER Nwell ;
        RECT 0.000 5.200 4.200 8.400 ;
      LAYER Metal1 ;
        RECT 0.000 7.800 4.200 8.400 ;
        RECT 0.550 5.750 0.800 7.800 ;
        RECT 2.250 5.750 2.500 7.800 ;
    END
  END VDD
  PIN VSS
    ANTENNADIFFAREA 1.607500 ;
    PORT
      LAYER Metal1 ;
        RECT 2.100 0.600 2.500 1.800 ;
        RECT 0.000 0.000 4.200 0.600 ;
    END
  END VSS
  OBS
      LAYER Metal1 ;
        RECT 1.400 4.650 1.650 7.450 ;
        RECT 3.100 5.450 3.350 7.450 ;
        RECT 3.100 5.400 3.600 5.450 ;
        RECT 3.100 5.100 3.750 5.400 ;
        RECT 3.100 5.050 3.650 5.100 ;
        RECT 1.300 4.350 2.850 4.650 ;
        RECT 0.450 3.700 0.950 4.000 ;
        RECT 1.350 2.150 1.600 4.350 ;
        RECT 1.850 3.000 2.350 3.300 ;
        RECT 0.700 1.900 1.600 2.150 ;
        RECT 0.700 0.950 0.950 1.900 ;
        RECT 3.100 0.950 3.350 5.050 ;
      LAYER Via1 ;
        RECT 3.350 5.100 3.650 5.400 ;
        RECT 1.400 4.350 1.700 4.650 ;
        RECT 2.450 4.350 2.750 4.650 ;
        RECT 0.550 3.700 0.850 4.000 ;
        RECT 1.950 3.000 2.250 3.300 ;
      LAYER Metal2 ;
        RECT 1.300 4.300 1.800 4.700 ;
        RECT 2.350 4.300 2.850 4.700 ;
  END
END gf180mcu_osu_sc_gp12t3v3__and2_1


MACRO gf180mcu_osu_sc_gp12t3v3__dffn_1
  CLASS BLOCK ;
  ORIGIN 0 0 ;
  FOREIGN gf180mcu_osu_sc_gp12t3v3__dffn_1 ;
  SIZE 14.350 BY 8.400 ;
  PIN D
    ANTENNAGATEAREA 0.765000 ;
    PORT
      LAYER Metal2 ;
        RECT 1.850 4.000 2.350 4.050 ;
        RECT 1.800 3.700 2.350 4.000 ;
        RECT 1.850 3.650 2.350 3.700 ;
    END
  END D
  PIN CLK
    ANTENNAGATEAREA 0.765000 ;
    PORT
      LAYER Metal2 ;
        RECT 9.600 3.300 10.000 3.350 ;
        RECT 9.550 3.000 10.050 3.300 ;
        RECT 9.600 2.950 10.000 3.000 ;
    END
  END CLK
  PIN Q
    ANTENNADIFFAREA 1.275000 ;
    PORT
      LAYER Metal2 ;
        RECT 13.450 5.400 13.850 5.450 ;
        RECT 13.400 5.100 13.900 5.400 ;
        RECT 13.450 5.050 13.850 5.100 ;
    END
  END Q
  PIN QN
    ANTENNAGATEAREA 0.765000 ;
    ANTENNADIFFAREA 1.275000 ;
    PORT
      LAYER Metal2 ;
        RECT 12.750 4.700 13.150 4.750 ;
        RECT 12.700 4.400 13.200 4.700 ;
        RECT 12.750 4.350 13.150 4.400 ;
    END
  END QN
  PIN VDD
    ANTENNADIFFAREA 8.642501 ;
    PORT
      LAYER Nwell ;
        RECT 0.000 5.200 14.350 8.400 ;
      LAYER Metal1 ;
        RECT 0.000 7.800 14.350 8.400 ;
        RECT 1.400 5.750 1.650 7.800 ;
        RECT 4.450 5.750 4.700 7.800 ;
        RECT 7.250 6.500 7.500 7.800 ;
        RECT 9.950 5.750 10.350 7.800 ;
        RECT 12.550 5.750 12.800 7.800 ;
    END
  END VDD
  PIN VSS
    ANTENNADIFFAREA 6.102500 ;
    PORT
      LAYER Metal1 ;
        RECT 1.400 0.600 1.650 1.800 ;
        RECT 4.450 0.600 4.700 1.400 ;
        RECT 7.250 0.600 7.500 1.800 ;
        RECT 9.950 0.600 10.350 1.450 ;
        RECT 12.550 0.600 12.800 1.800 ;
        RECT 0.000 0.000 14.350 0.600 ;
    END
  END VSS
  OBS
      LAYER Metal1 ;
        RECT 0.550 2.600 0.800 7.450 ;
        RECT 3.050 5.400 3.300 7.450 ;
        RECT 5.850 6.500 6.100 7.450 ;
        RECT 1.400 5.150 3.300 5.400 ;
        RECT 4.950 6.250 6.100 6.500 ;
        RECT 8.100 6.250 8.350 7.450 ;
        RECT 1.400 4.650 1.650 5.150 ;
        RECT 4.050 5.000 4.550 5.300 ;
        RECT 1.050 4.350 1.650 4.650 ;
        RECT 2.600 4.350 3.100 4.650 ;
        RECT 1.350 4.250 1.650 4.350 ;
        RECT 2.700 4.300 3.000 4.350 ;
        RECT 1.350 3.450 1.600 4.250 ;
        RECT 1.850 3.700 2.350 4.000 ;
        RECT 1.350 3.100 1.650 3.450 ;
        RECT 0.500 2.100 0.800 2.600 ;
        RECT 1.400 2.500 1.650 3.100 ;
        RECT 4.150 2.500 4.450 5.000 ;
        RECT 4.950 3.900 5.200 6.250 ;
        RECT 8.100 5.950 8.400 6.250 ;
        RECT 9.100 6.000 9.350 7.450 ;
        RECT 6.000 5.750 8.400 5.950 ;
        RECT 8.950 5.750 9.350 6.000 ;
        RECT 6.000 5.650 8.350 5.750 ;
        RECT 6.000 5.300 6.300 5.650 ;
        RECT 5.900 5.000 6.400 5.300 ;
        RECT 6.700 5.000 7.200 5.300 ;
        RECT 8.100 5.200 8.350 5.650 ;
        RECT 4.900 3.650 5.200 3.900 ;
        RECT 5.500 4.350 6.550 4.650 ;
        RECT 1.400 2.250 2.400 2.500 ;
        RECT 0.550 0.950 0.800 2.100 ;
        RECT 2.000 1.800 2.400 2.250 ;
        RECT 4.050 2.200 4.550 2.500 ;
        RECT 4.900 1.850 5.150 3.650 ;
        RECT 5.500 2.450 5.800 4.350 ;
        RECT 6.800 4.000 7.100 5.000 ;
        RECT 8.100 4.950 8.700 5.200 ;
        RECT 7.650 4.350 8.150 4.650 ;
        RECT 8.400 4.000 8.700 4.950 ;
        RECT 6.750 3.700 7.250 4.000 ;
        RECT 8.100 3.750 8.700 4.000 ;
        RECT 5.400 2.150 5.900 2.450 ;
        RECT 2.000 1.550 3.300 1.800 ;
        RECT 4.900 1.600 6.250 1.850 ;
        RECT 3.050 0.950 3.300 1.550 ;
        RECT 5.850 1.550 6.250 1.600 ;
        RECT 5.850 0.950 6.100 1.550 ;
        RECT 8.100 0.950 8.350 3.750 ;
        RECT 8.950 1.850 9.250 5.750 ;
        RECT 10.300 5.300 10.600 5.400 ;
        RECT 10.200 5.000 10.700 5.300 ;
        RECT 9.650 3.300 9.950 3.400 ;
        RECT 9.550 3.000 10.050 3.300 ;
        RECT 9.650 2.900 9.950 3.000 ;
        RECT 10.300 2.000 10.600 5.000 ;
        RECT 10.950 3.350 11.200 7.450 ;
        RECT 11.700 4.650 11.950 7.450 ;
        RECT 13.400 5.450 13.650 7.450 ;
        RECT 13.400 5.100 13.900 5.450 ;
        RECT 13.400 5.050 13.850 5.100 ;
        RECT 13.400 4.950 13.700 5.050 ;
        RECT 12.700 4.650 13.200 4.700 ;
        RECT 11.700 4.400 13.200 4.650 ;
        RECT 11.700 4.350 13.100 4.400 ;
        RECT 12.800 4.300 13.100 4.350 ;
        RECT 10.950 3.050 12.400 3.350 ;
        RECT 8.950 1.600 9.350 1.850 ;
        RECT 10.200 1.700 10.700 2.000 ;
        RECT 9.100 0.950 9.350 1.600 ;
        RECT 10.950 0.950 11.200 3.050 ;
        RECT 12.800 2.300 13.050 4.300 ;
        RECT 13.450 4.050 13.700 4.950 ;
        RECT 11.700 2.050 13.050 2.300 ;
        RECT 13.400 3.750 13.700 4.050 ;
        RECT 11.700 0.950 11.950 2.050 ;
        RECT 13.400 0.950 13.650 3.750 ;
      LAYER Via1 ;
        RECT 2.700 4.350 3.000 4.650 ;
        RECT 1.950 3.700 2.250 4.000 ;
        RECT 0.500 2.200 0.800 2.500 ;
        RECT 6.800 5.000 7.100 5.300 ;
        RECT 6.150 4.350 6.450 4.650 ;
        RECT 4.150 2.200 4.450 2.500 ;
        RECT 7.750 4.350 8.050 4.650 ;
        RECT 6.850 3.700 7.150 4.000 ;
        RECT 8.950 4.350 9.250 4.650 ;
        RECT 9.650 3.000 9.950 3.300 ;
        RECT 13.500 5.100 13.800 5.400 ;
        RECT 12.800 4.400 13.100 4.700 ;
        RECT 12.000 3.050 12.300 3.350 ;
        RECT 10.300 1.700 10.600 2.000 ;
      LAYER Metal2 ;
        RECT 6.750 5.300 7.150 5.350 ;
        RECT 6.700 5.000 11.150 5.300 ;
        RECT 6.750 4.950 7.150 5.000 ;
        RECT 2.600 4.650 3.050 4.700 ;
        RECT 6.050 4.650 6.550 4.700 ;
        RECT 7.700 4.650 8.100 4.700 ;
        RECT 8.900 4.650 9.300 4.700 ;
        RECT 2.600 4.350 9.350 4.650 ;
        RECT 2.600 4.300 3.050 4.350 ;
        RECT 6.050 4.300 6.550 4.350 ;
        RECT 7.700 4.300 8.100 4.350 ;
        RECT 8.900 4.300 9.300 4.350 ;
        RECT 6.800 4.000 7.200 4.050 ;
        RECT 6.750 3.700 7.250 4.000 ;
        RECT 6.800 3.650 7.200 3.700 ;
        RECT 10.850 3.350 11.150 5.000 ;
        RECT 11.950 3.350 12.350 3.400 ;
        RECT 10.850 3.050 12.400 3.350 ;
        RECT 11.950 3.000 12.350 3.050 ;
        RECT 0.450 2.500 0.850 2.550 ;
        RECT 4.100 2.500 4.500 2.550 ;
        RECT 0.400 2.200 4.550 2.500 ;
        RECT 0.450 2.150 0.850 2.200 ;
        RECT 4.100 2.150 4.500 2.200 ;
        RECT 10.250 2.000 10.650 2.050 ;
        RECT 5.800 1.850 6.200 1.900 ;
        RECT 9.500 1.850 10.700 2.000 ;
        RECT 5.750 1.700 10.700 1.850 ;
        RECT 5.750 1.650 10.650 1.700 ;
        RECT 5.750 1.550 9.900 1.650 ;
        RECT 5.800 1.500 6.200 1.550 ;
  END
END gf180mcu_osu_sc_gp12t3v3__dffn_1


MACRO gf180mcu_osu_sc_gp12t3v3__fill_16
  CLASS BLOCK ;
  ORIGIN 0 0 ;
  FOREIGN gf180mcu_osu_sc_gp12t3v3__fill_16 ;
  SIZE 5.250 BY 8.400 ;
  PIN VDD
    PORT
      LAYER Metal1 ;
        RECT 0.000 7.800 5.250 8.400 ;
    END
  END VDD
  PIN VSS
    PORT
      LAYER Metal1 ;
        RECT 0.000 0.000 5.250 0.600 ;
    END
  END VSS
  OBS
      LAYER Nwell ;
        RECT 0.000 5.200 5.250 8.400 ;
  END
END gf180mcu_osu_sc_gp12t3v3__fill_16


MACRO gf180mcu_osu_sc_gp12t3v3__xnor2_1
  CLASS BLOCK ;
  ORIGIN 0 0 ;
  FOREIGN gf180mcu_osu_sc_gp12t3v3__xnor2_1 ;
  SIZE 6.300 BY 8.400 ;
  PIN A
    ANTENNAGATEAREA 1.530000 ;
    PORT
      LAYER Metal2 ;
        RECT 3.650 4.050 3.950 4.100 ;
        RECT 3.600 3.650 4.000 4.050 ;
        RECT 1.200 2.450 1.600 2.650 ;
        RECT 1.200 2.250 1.650 2.450 ;
        RECT 1.250 2.150 1.650 2.250 ;
        RECT 1.350 1.200 1.650 2.150 ;
        RECT 3.650 1.200 3.950 3.650 ;
        RECT 1.350 0.900 3.950 1.200 ;
    END
  END A
  PIN B
    ANTENNAGATEAREA 1.530000 ;
    PORT
      LAYER Metal2 ;
        RECT 4.400 2.650 4.700 2.700 ;
        RECT 4.350 2.600 4.750 2.650 ;
        RECT 4.300 2.300 4.800 2.600 ;
        RECT 4.350 2.250 4.750 2.300 ;
        RECT 4.400 2.200 4.700 2.250 ;
    END
  END B
  PIN Y
    ANTENNADIFFAREA 2.175000 ;
    PORT
      LAYER Metal2 ;
        RECT 2.900 5.750 3.400 6.200 ;
        RECT 2.900 5.700 3.300 5.750 ;
        RECT 2.900 1.900 3.200 5.700 ;
        RECT 2.800 1.500 3.300 1.900 ;
    END
  END Y
  PIN VDD
    ANTENNADIFFAREA 3.557500 ;
    PORT
      LAYER Nwell ;
        RECT 0.000 5.200 6.300 8.400 ;
      LAYER Metal1 ;
        RECT 0.000 7.800 6.300 8.400 ;
        RECT 1.400 5.750 1.650 7.800 ;
        RECT 4.500 5.750 4.750 7.800 ;
    END
  END VDD
  PIN VSS
    ANTENNADIFFAREA 2.622500 ;
    PORT
      LAYER Metal1 ;
        RECT 1.400 0.600 1.650 1.800 ;
        RECT 4.500 0.600 4.750 1.800 ;
        RECT 0.000 0.000 6.300 0.600 ;
    END
  END VSS
  OBS
      LAYER Metal1 ;
        RECT 0.550 4.000 0.800 7.450 ;
        RECT 2.950 6.200 3.200 7.450 ;
        RECT 2.900 5.700 3.300 6.200 ;
        RECT 2.900 5.600 3.200 5.700 ;
        RECT 5.350 4.650 5.600 7.450 ;
        RECT 2.550 4.350 5.600 4.650 ;
        RECT 0.550 3.700 3.300 4.000 ;
        RECT 3.550 3.700 4.050 4.000 ;
        RECT 0.550 0.950 0.800 3.700 ;
        RECT 1.150 2.300 1.650 2.600 ;
        RECT 3.000 2.500 3.300 3.700 ;
        RECT 2.900 2.200 3.400 2.500 ;
        RECT 4.300 2.300 4.800 2.600 ;
        RECT 2.900 1.400 3.200 1.950 ;
        RECT 2.950 0.950 3.200 1.400 ;
        RECT 5.350 0.950 5.600 4.350 ;
      LAYER Via1 ;
        RECT 3.000 5.800 3.300 6.100 ;
        RECT 3.650 3.700 3.950 4.000 ;
        RECT 1.250 2.300 1.550 2.600 ;
        RECT 4.400 2.300 4.700 2.600 ;
        RECT 2.900 1.550 3.200 1.850 ;
  END
END gf180mcu_osu_sc_gp12t3v3__xnor2_1


MACRO gf180mcu_osu_sc_gp12t3v3__fill_8
  CLASS BLOCK ;
  ORIGIN 0 0 ;
  FOREIGN gf180mcu_osu_sc_gp12t3v3__fill_8 ;
  SIZE 2.800 BY 8.400 ;
  PIN VDD
    PORT
      LAYER Metal1 ;
        RECT 0.000 7.800 2.800 8.400 ;
    END
  END VDD
  PIN VSS
    PORT
      LAYER Metal1 ;
        RECT 0.000 0.000 2.800 0.600 ;
    END
  END VSS
  OBS
      LAYER Nwell ;
        RECT 0.000 5.200 2.800 8.400 ;
  END
END gf180mcu_osu_sc_gp12t3v3__fill_8


MACRO gf180mcu_osu_sc_gp12t3v3__nand2_1
  CLASS BLOCK ;
  ORIGIN 0 0 ;
  FOREIGN gf180mcu_osu_sc_gp12t3v3__nand2_1 ;
  SIZE 3.150 BY 8.400 ;
  PIN A
    ANTENNAGATEAREA 0.765000 ;
    PORT
      LAYER Metal2 ;
        RECT 0.450 3.650 0.950 4.050 ;
    END
  END A
  PIN B
    ANTENNAGATEAREA 0.765000 ;
    PORT
      LAYER Metal2 ;
        RECT 2.200 2.950 2.700 3.350 ;
    END
  END B
  PIN Y
    ANTENNADIFFAREA 1.360000 ;
    PORT
      LAYER Metal2 ;
        RECT 1.500 4.350 2.000 4.750 ;
    END
  END Y
  PIN VDD
    ANTENNADIFFAREA 2.375000 ;
    PORT
      LAYER Nwell ;
        RECT 0.000 5.200 3.150 8.400 ;
      LAYER Metal1 ;
        RECT 0.000 7.800 3.150 8.400 ;
        RECT 0.550 5.750 0.800 7.800 ;
        RECT 2.250 5.750 2.500 7.800 ;
    END
  END VDD
  PIN VSS
    ANTENNADIFFAREA 1.100000 ;
    PORT
      LAYER Metal1 ;
        RECT 2.100 0.600 2.350 1.800 ;
        RECT 0.000 0.000 3.150 0.600 ;
    END
  END VSS
  OBS
      LAYER Metal1 ;
        RECT 1.400 4.750 1.650 7.450 ;
        RECT 1.400 4.350 2.000 4.750 ;
        RECT 0.450 3.700 0.950 4.000 ;
        RECT 1.400 2.150 1.650 4.350 ;
        RECT 2.200 3.000 2.700 3.300 ;
        RECT 0.700 1.900 1.650 2.150 ;
        RECT 0.700 0.950 0.950 1.900 ;
      LAYER Via1 ;
        RECT 1.600 4.400 1.900 4.700 ;
        RECT 0.550 3.700 0.850 4.000 ;
        RECT 2.300 3.000 2.600 3.300 ;
  END
END gf180mcu_osu_sc_gp12t3v3__nand2_1


MACRO gf180mcu_osu_sc_gp12t3v3__clkinv_4
  CLASS BLOCK ;
  ORIGIN 0 0 ;
  FOREIGN gf180mcu_osu_sc_gp12t3v3__clkinv_4 ;
  SIZE 4.900 BY 8.400 ;
  PIN A
    ANTENNAGATEAREA 3.060000 ;
    PORT
      LAYER Metal2 ;
        RECT 0.450 3.650 0.950 4.050 ;
    END
  END A
  PIN Y
    ANTENNADIFFAREA 2.805000 ;
    PORT
      LAYER Metal2 ;
        RECT 3.250 5.050 3.750 5.450 ;
    END
  END Y
  PIN VDD
    ANTENNADIFFAREA 3.647500 ;
    PORT
      LAYER Nwell ;
        RECT 0.000 5.200 4.900 8.400 ;
      LAYER Metal1 ;
        RECT 0.000 7.800 4.900 8.400 ;
        RECT 0.550 5.750 0.800 7.800 ;
        RECT 2.250 5.750 2.500 7.800 ;
        RECT 3.950 5.750 4.200 7.800 ;
    END
  END VDD
  PIN VSS
    ANTENNADIFFAREA 2.330000 ;
    PORT
      LAYER Metal1 ;
        RECT 0.550 0.600 0.800 1.800 ;
        RECT 2.250 0.600 2.500 1.800 ;
        RECT 3.950 0.600 4.200 1.800 ;
        RECT 0.000 0.000 4.900 0.600 ;
    END
  END VSS
  OBS
      LAYER Metal1 ;
        RECT 1.400 4.900 1.650 7.450 ;
        RECT 3.100 5.450 3.350 7.450 ;
        RECT 3.100 5.050 3.750 5.450 ;
        RECT 3.100 4.900 3.350 5.050 ;
        RECT 1.400 4.650 3.350 4.900 ;
        RECT 0.450 3.700 0.950 4.000 ;
        RECT 1.400 2.300 1.650 4.650 ;
        RECT 3.100 2.300 3.350 4.650 ;
        RECT 1.400 2.050 3.350 2.300 ;
        RECT 1.400 0.950 1.650 2.050 ;
        RECT 3.100 0.950 3.350 2.050 ;
      LAYER Via1 ;
        RECT 3.350 5.100 3.650 5.400 ;
        RECT 0.550 3.700 0.850 4.000 ;
  END
END gf180mcu_osu_sc_gp12t3v3__clkinv_4


MACRO gf180mcu_osu_sc_gp12t3v3__inv_4
  CLASS BLOCK ;
  ORIGIN 0 0 ;
  FOREIGN gf180mcu_osu_sc_gp12t3v3__inv_4 ;
  SIZE 4.900 BY 8.400 ;
  PIN A
    ANTENNAGATEAREA 3.060000 ;
    PORT
      LAYER Metal2 ;
        RECT 0.450 3.650 0.950 4.050 ;
    END
  END A
  PIN Y
    ANTENNADIFFAREA 2.805000 ;
    PORT
      LAYER Metal2 ;
        RECT 3.250 5.050 3.750 5.450 ;
    END
  END Y
  PIN VDD
    ANTENNADIFFAREA 3.647500 ;
    PORT
      LAYER Nwell ;
        RECT 0.000 5.200 4.900 8.400 ;
      LAYER Metal1 ;
        RECT 0.000 7.800 4.900 8.400 ;
        RECT 0.550 5.750 0.800 7.800 ;
        RECT 2.250 5.750 2.500 7.800 ;
        RECT 3.950 5.750 4.200 7.800 ;
    END
  END VDD
  PIN VSS
    ANTENNADIFFAREA 2.330000 ;
    PORT
      LAYER Metal1 ;
        RECT 0.550 0.600 0.800 1.800 ;
        RECT 2.250 0.600 2.500 1.800 ;
        RECT 3.950 0.600 4.200 1.800 ;
        RECT 0.000 0.000 4.900 0.600 ;
    END
  END VSS
  OBS
      LAYER Metal1 ;
        RECT 1.400 4.900 1.650 7.450 ;
        RECT 3.100 5.450 3.350 7.450 ;
        RECT 3.100 5.050 3.700 5.450 ;
        RECT 3.100 4.900 3.350 5.050 ;
        RECT 1.400 4.650 3.350 4.900 ;
        RECT 0.450 3.700 0.950 4.000 ;
        RECT 1.400 2.300 1.650 4.650 ;
        RECT 3.100 2.300 3.350 4.650 ;
        RECT 1.400 2.050 3.350 2.300 ;
        RECT 1.400 0.950 1.650 2.050 ;
        RECT 3.100 0.950 3.350 2.050 ;
      LAYER Via1 ;
        RECT 3.350 5.100 3.650 5.400 ;
        RECT 0.550 3.700 0.850 4.000 ;
  END
END gf180mcu_osu_sc_gp12t3v3__inv_4


MACRO gf180mcu_osu_sc_gp12t3v3__tieh
  CLASS BLOCK ;
  ORIGIN 0 0 ;
  FOREIGN gf180mcu_osu_sc_gp12t3v3__tieh ;
  SIZE 2.450 BY 8.400 ;
  PIN Y
    ANTENNADIFFAREA 0.850000 ;
    PORT
      LAYER Metal2 ;
        RECT 1.500 5.050 2.000 5.450 ;
    END
  END Y
  PIN VDD
    ANTENNADIFFAREA 1.187500 ;
    PORT
      LAYER Nwell ;
        RECT 0.000 5.200 2.450 8.400 ;
      LAYER Metal1 ;
        RECT 0.000 7.800 2.450 8.400 ;
        RECT 0.550 5.750 0.800 7.800 ;
    END
  END VDD
  PIN VSS
    ANTENNADIFFAREA 0.762500 ;
    PORT
      LAYER Metal1 ;
        RECT 0.550 0.600 0.800 1.800 ;
        RECT 0.000 0.000 2.450 0.600 ;
    END
  END VSS
  OBS
      LAYER Metal1 ;
        RECT 1.400 5.450 1.650 7.450 ;
        RECT 1.400 5.400 1.850 5.450 ;
        RECT 1.400 5.100 2.000 5.400 ;
        RECT 1.600 5.050 1.850 5.100 ;
        RECT 1.150 2.200 1.650 2.450 ;
        RECT 1.400 0.950 1.650 2.200 ;
      LAYER Via1 ;
        RECT 1.600 5.100 1.900 5.400 ;
  END
END gf180mcu_osu_sc_gp12t3v3__tieh


MACRO gf180mcu_osu_sc_gp12t3v3__lshifup
  CLASS BLOCK ;
  ORIGIN 0 0 ;
  FOREIGN gf180mcu_osu_sc_gp12t3v3__lshifup ;
  SIZE 8.050 BY 8.400 ;
  PIN A
    ANTENNAGATEAREA 1.020000 ;
    PORT
      LAYER Metal2 ;
        RECT 0.450 2.600 0.950 2.650 ;
        RECT 4.000 2.600 4.500 2.650 ;
        RECT 0.450 2.300 4.500 2.600 ;
        RECT 0.450 2.250 0.950 2.300 ;
        RECT 4.000 2.250 4.500 2.300 ;
    END
  END A
  PIN Y
    ANTENNADIFFAREA 1.402500 ;
    PORT
      LAYER Metal2 ;
        RECT 7.100 5.050 7.600 5.450 ;
    END
  END Y
  PIN VDDH
    ANTENNADIFFAREA 3.305000 ;
    PORT
      LAYER Nwell ;
        RECT 2.900 5.200 8.050 8.400 ;
      LAYER Metal1 ;
        RECT 2.900 7.800 8.050 8.400 ;
        RECT 4.350 5.750 4.650 7.800 ;
        RECT 6.050 5.750 6.350 7.800 ;
    END
  END VDDH
  PIN VDD
    ANTENNADIFFAREA 1.272500 ;
    PORT
      LAYER Nwell ;
        RECT 0.000 5.200 2.300 8.400 ;
      LAYER Metal1 ;
        RECT 0.000 7.800 2.300 8.400 ;
        RECT 0.550 5.750 0.850 7.800 ;
    END
  END VDD
  PIN VSS
    ANTENNADIFFAREA 3.470000 ;
    PORT
      LAYER Metal1 ;
        RECT 0.550 0.600 0.850 1.800 ;
        RECT 4.350 0.600 4.650 1.800 ;
        RECT 6.050 0.600 6.350 1.800 ;
        RECT 0.000 0.000 8.050 0.600 ;
    END
  END VSS
  OBS
      LAYER Metal1 ;
        RECT 1.450 3.550 1.750 7.450 ;
        RECT 3.450 5.300 3.750 7.450 ;
        RECT 4.550 5.300 5.000 5.400 ;
        RECT 3.450 5.000 5.000 5.300 ;
        RECT 1.350 3.250 1.850 3.550 ;
        RECT 0.450 2.300 0.950 2.600 ;
        RECT 1.450 0.950 1.750 3.250 ;
        RECT 3.450 0.950 3.750 5.000 ;
        RECT 4.550 4.950 5.000 5.000 ;
        RECT 5.250 4.650 5.550 7.450 ;
        RECT 6.950 5.450 7.250 7.450 ;
        RECT 6.950 5.400 7.500 5.450 ;
        RECT 6.100 5.000 6.600 5.300 ;
        RECT 6.950 5.100 7.550 5.400 ;
        RECT 6.950 5.050 7.500 5.100 ;
        RECT 4.800 4.200 5.550 4.650 ;
        RECT 4.500 3.250 5.000 3.550 ;
        RECT 4.000 2.300 4.500 2.600 ;
        RECT 5.250 0.950 5.550 4.200 ;
        RECT 6.950 0.950 7.250 5.050 ;
      LAYER Via1 ;
        RECT 4.600 5.000 4.900 5.300 ;
        RECT 1.450 3.250 1.750 3.550 ;
        RECT 0.550 2.300 0.850 2.600 ;
        RECT 6.200 5.000 6.500 5.300 ;
        RECT 7.200 5.100 7.500 5.400 ;
        RECT 4.600 3.250 4.900 3.550 ;
        RECT 4.100 2.300 4.400 2.600 ;
      LAYER Metal2 ;
        RECT 4.550 5.300 4.950 5.350 ;
        RECT 6.100 5.300 6.600 5.350 ;
        RECT 4.500 5.000 6.600 5.300 ;
        RECT 4.550 4.950 4.950 5.000 ;
        RECT 6.100 4.950 6.600 5.000 ;
        RECT 1.350 3.550 1.850 3.600 ;
        RECT 4.500 3.550 5.000 3.600 ;
        RECT 1.350 3.250 5.000 3.550 ;
        RECT 1.350 3.200 1.850 3.250 ;
        RECT 4.500 3.200 5.000 3.250 ;
  END
END gf180mcu_osu_sc_gp12t3v3__lshifup


MACRO gf180mcu_osu_sc_gp12t3v3__dlatn_1
  CLASS BLOCK ;
  ORIGIN 0 0 ;
  FOREIGN gf180mcu_osu_sc_gp12t3v3__dlatn_1 ;
  SIZE 10.850 BY 8.400 ;
  PIN D
    ANTENNAGATEAREA 0.765000 ;
    PORT
      LAYER Metal2 ;
        RECT 1.850 4.350 2.350 4.750 ;
    END
  END D
  PIN CLK
    ANTENNAGATEAREA 0.765000 ;
    PORT
      LAYER Metal2 ;
        RECT 7.100 2.950 7.600 3.350 ;
    END
  END CLK
  PIN Q
    ANTENNADIFFAREA 1.275000 ;
    PORT
      LAYER Metal2 ;
        RECT 9.950 5.400 10.350 5.450 ;
        RECT 9.900 5.100 10.400 5.400 ;
        RECT 9.950 5.050 10.350 5.100 ;
    END
  END Q
  PIN VDD
    ANTENNADIFFAREA 6.355000 ;
    PORT
      LAYER Nwell ;
        RECT 0.000 5.200 10.850 8.400 ;
      LAYER Metal1 ;
        RECT 0.000 7.800 10.850 8.400 ;
        RECT 1.450 6.550 1.700 7.800 ;
        RECT 4.850 5.750 5.100 7.800 ;
        RECT 7.400 5.750 7.650 7.800 ;
        RECT 9.000 5.750 9.250 7.800 ;
    END
  END VDD
  PIN VSS
    ANTENNADIFFAREA 4.782500 ;
    PORT
      LAYER Metal1 ;
        RECT 1.450 0.600 1.850 1.800 ;
        RECT 4.700 0.600 5.100 1.800 ;
        RECT 7.400 0.600 7.650 1.800 ;
        RECT 9.000 0.600 9.250 1.800 ;
        RECT 0.000 0.000 10.850 0.600 ;
    END
  END VSS
  OBS
      LAYER Metal1 ;
        RECT 0.600 4.050 0.850 7.450 ;
        RECT 3.150 6.000 3.400 7.450 ;
        RECT 1.150 5.750 3.400 6.000 ;
        RECT 5.700 5.800 5.950 7.450 ;
        RECT 1.150 4.650 1.400 5.750 ;
        RECT 5.700 5.450 6.200 5.800 ;
        RECT 2.600 4.900 3.100 5.200 ;
        RECT 1.100 4.350 1.550 4.650 ;
        RECT 1.850 4.400 2.350 4.700 ;
        RECT 0.500 4.000 0.850 4.050 ;
        RECT 0.350 3.700 0.850 4.000 ;
        RECT 0.450 3.650 0.850 3.700 ;
        RECT 0.600 0.950 0.850 3.650 ;
        RECT 1.150 2.300 1.400 4.350 ;
        RECT 2.700 2.850 3.000 4.900 ;
        RECT 3.450 4.350 3.950 4.650 ;
        RECT 5.200 4.350 5.700 4.650 ;
        RECT 4.500 3.700 5.000 4.000 ;
        RECT 5.950 2.850 6.200 5.450 ;
        RECT 6.550 4.700 6.800 7.450 ;
        RECT 8.150 5.500 8.400 7.450 ;
        RECT 8.150 5.300 8.550 5.500 ;
        RECT 9.850 5.450 10.100 7.450 ;
        RECT 9.850 5.400 10.300 5.450 ;
        RECT 8.150 5.250 8.650 5.300 ;
        RECT 8.150 5.000 9.500 5.250 ;
        RECT 8.150 4.950 8.550 5.000 ;
        RECT 6.550 4.650 6.950 4.700 ;
        RECT 6.450 4.350 6.950 4.650 ;
        RECT 2.700 2.550 6.200 2.850 ;
        RECT 1.150 2.050 3.400 2.300 ;
        RECT 5.950 2.200 6.200 2.550 ;
        RECT 3.150 0.950 3.400 2.050 ;
        RECT 5.700 1.950 6.200 2.200 ;
        RECT 6.550 4.300 6.950 4.350 ;
        RECT 5.700 0.950 5.950 1.950 ;
        RECT 6.550 0.950 6.800 4.300 ;
        RECT 8.450 3.700 8.950 4.000 ;
        RECT 7.100 3.000 7.600 3.300 ;
        RECT 9.200 2.300 9.500 5.000 ;
        RECT 8.150 2.050 9.500 2.300 ;
        RECT 9.850 5.100 10.400 5.400 ;
        RECT 9.850 5.050 10.300 5.100 ;
        RECT 8.150 0.950 8.400 2.050 ;
        RECT 9.850 0.950 10.100 5.050 ;
      LAYER Via1 ;
        RECT 1.950 4.400 2.250 4.700 ;
        RECT 0.450 3.700 0.750 4.000 ;
        RECT 3.550 4.350 3.850 4.650 ;
        RECT 5.300 4.350 5.600 4.650 ;
        RECT 4.600 3.700 4.900 4.000 ;
        RECT 8.250 5.000 8.550 5.300 ;
        RECT 6.550 4.350 6.850 4.650 ;
        RECT 8.550 3.700 8.850 4.000 ;
        RECT 7.200 3.000 7.500 3.300 ;
        RECT 10.000 5.100 10.300 5.400 ;
      LAYER Metal2 ;
        RECT 8.200 5.300 8.600 5.350 ;
        RECT 8.150 5.000 8.650 5.300 ;
        RECT 8.200 4.950 8.600 5.000 ;
        RECT 3.500 4.650 3.900 4.700 ;
        RECT 5.200 4.650 5.700 4.700 ;
        RECT 6.450 4.650 6.950 4.700 ;
        RECT 3.450 4.350 6.950 4.650 ;
        RECT 3.500 4.300 3.900 4.350 ;
        RECT 5.200 4.300 5.700 4.350 ;
        RECT 6.450 4.300 6.950 4.350 ;
        RECT 0.350 4.000 0.850 4.050 ;
        RECT 4.550 4.000 4.950 4.050 ;
        RECT 8.450 4.000 8.950 4.050 ;
        RECT 0.350 3.700 8.950 4.000 ;
        RECT 0.350 3.650 0.850 3.700 ;
        RECT 4.550 3.650 4.950 3.700 ;
        RECT 8.450 3.650 8.950 3.700 ;
  END
END gf180mcu_osu_sc_gp12t3v3__dlatn_1


MACRO gf180mcu_osu_sc_gp12t3v3__buf_2
  CLASS BLOCK ;
  ORIGIN 0 0 ;
  FOREIGN gf180mcu_osu_sc_gp12t3v3__buf_2 ;
  SIZE 4.200 BY 8.400 ;
  PIN A
    ANTENNAGATEAREA 0.765000 ;
    PORT
      LAYER Metal2 ;
        RECT 0.850 4.700 1.250 4.750 ;
        RECT 0.800 4.400 1.300 4.700 ;
        RECT 0.850 4.350 1.250 4.400 ;
    END
  END A
  PIN Y
    ANTENNADIFFAREA 1.402500 ;
    PORT
      LAYER Metal2 ;
        RECT 2.200 5.050 2.700 5.450 ;
    END
  END Y
  PIN VDD
    ANTENNADIFFAREA 2.460000 ;
    PORT
      LAYER Nwell ;
        RECT 0.000 5.200 4.200 8.400 ;
      LAYER Metal1 ;
        RECT 0.000 7.800 4.200 8.400 ;
        RECT 1.400 5.750 1.650 7.800 ;
        RECT 3.100 5.750 3.350 7.800 ;
    END
  END VDD
  PIN VSS
    ANTENNADIFFAREA 1.567500 ;
    PORT
      LAYER Metal1 ;
        RECT 1.400 0.600 1.650 1.800 ;
        RECT 3.100 0.600 3.350 1.800 ;
        RECT 0.000 0.000 4.200 0.600 ;
    END
  END VSS
  OBS
      LAYER Metal1 ;
        RECT 0.550 6.100 0.800 7.450 ;
        RECT 0.300 5.750 0.800 6.100 ;
        RECT 0.300 3.650 0.550 5.750 ;
        RECT 2.250 5.500 2.500 7.450 ;
        RECT 2.250 5.400 2.550 5.500 ;
        RECT 2.200 5.100 2.700 5.400 ;
        RECT 2.250 5.050 2.550 5.100 ;
        RECT 0.800 4.400 1.300 4.700 ;
        RECT 0.300 3.400 0.800 3.650 ;
        RECT 0.550 3.100 2.000 3.400 ;
        RECT 0.550 0.950 0.800 3.100 ;
        RECT 2.250 0.950 2.500 5.050 ;
      LAYER Via1 ;
        RECT 2.300 5.100 2.600 5.400 ;
        RECT 0.900 4.400 1.200 4.700 ;
  END
END gf180mcu_osu_sc_gp12t3v3__buf_2


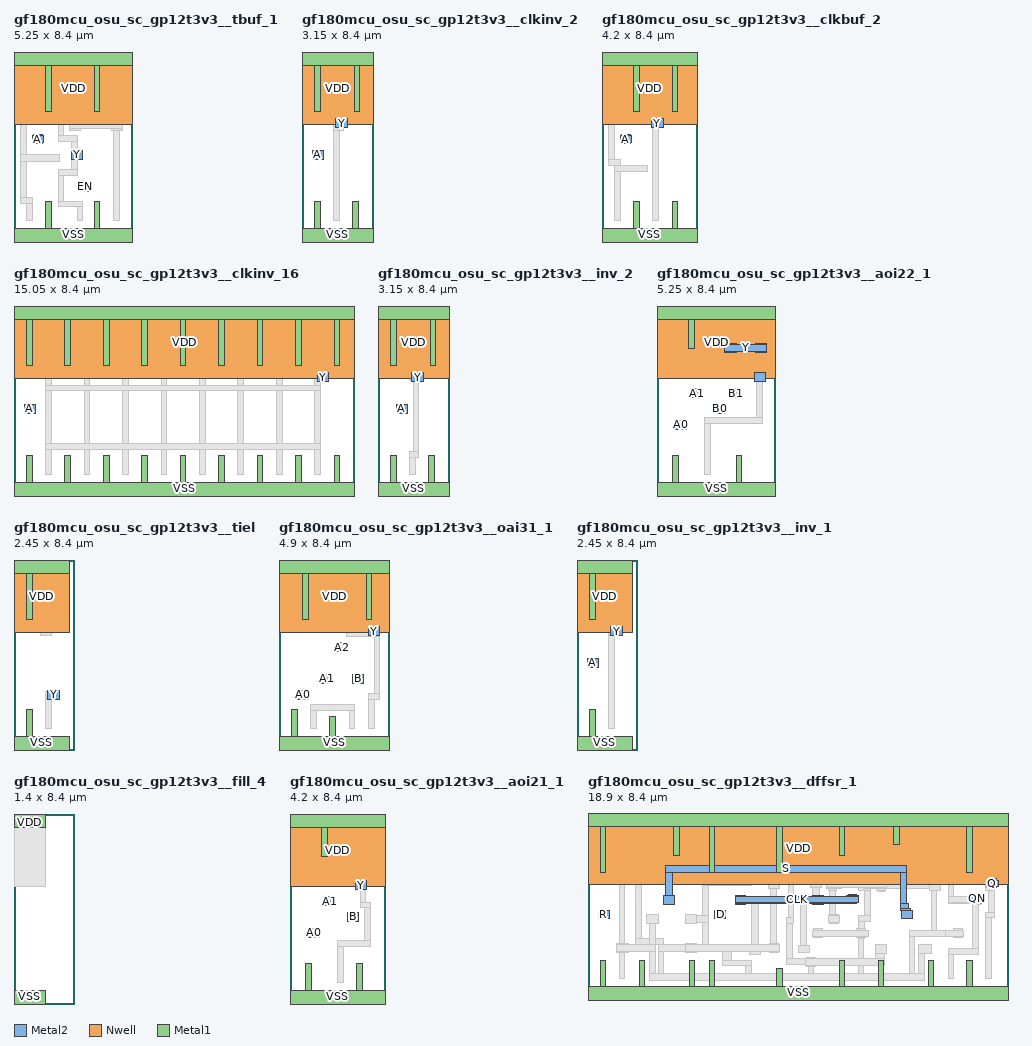
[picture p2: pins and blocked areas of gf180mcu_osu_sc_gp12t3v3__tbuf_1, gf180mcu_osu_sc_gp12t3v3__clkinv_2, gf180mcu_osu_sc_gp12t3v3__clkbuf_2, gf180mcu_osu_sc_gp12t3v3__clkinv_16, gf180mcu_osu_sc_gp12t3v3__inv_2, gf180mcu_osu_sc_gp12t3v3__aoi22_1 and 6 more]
MACRO gf180mcu_osu_sc_gp12t3v3__tbuf_1
  CLASS BLOCK ;
  ORIGIN 0 0 ;
  FOREIGN gf180mcu_osu_sc_gp12t3v3__tbuf_1 ;
  SIZE 5.250 BY 8.400 ;
  PIN A
    ANTENNAGATEAREA 0.765000 ;
    PORT
      LAYER Metal2 ;
        RECT 0.850 4.700 1.250 4.750 ;
        RECT 0.800 4.400 1.300 4.700 ;
        RECT 0.850 4.350 1.250 4.400 ;
    END
  END A
  PIN EN
    ANTENNAGATEAREA 1.020000 ;
    PORT
      LAYER Metal2 ;
        RECT 2.900 2.250 3.400 2.650 ;
    END
  END EN
  PIN Y
    ANTENNADIFFAREA 1.275000 ;
    PORT
      LAYER Metal2 ;
        RECT 2.550 3.650 3.050 4.050 ;
    END
  END Y
  PIN VDD
    ANTENNADIFFAREA 3.135000 ;
    PORT
      LAYER Nwell ;
        RECT 0.000 5.200 5.250 8.400 ;
      LAYER Metal1 ;
        RECT 0.000 7.800 5.250 8.400 ;
        RECT 1.400 5.750 1.650 7.800 ;
        RECT 3.550 5.750 3.800 7.800 ;
    END
  END VDD
  PIN VSS
    ANTENNADIFFAREA 2.242500 ;
    PORT
      LAYER Metal1 ;
        RECT 1.400 0.600 1.650 1.800 ;
        RECT 3.550 0.600 3.800 1.800 ;
        RECT 0.000 0.000 5.250 0.600 ;
    END
  END VSS
  OBS
      LAYER Metal1 ;
        RECT 0.550 6.100 0.800 7.450 ;
        RECT 0.300 5.750 0.800 6.100 ;
        RECT 2.800 6.000 3.050 7.450 ;
        RECT 1.950 5.750 3.050 6.000 ;
        RECT 0.300 3.850 0.550 5.750 ;
        RECT 1.950 4.700 2.200 5.750 ;
        RECT 4.400 5.300 4.650 7.450 ;
        RECT 2.450 5.000 2.950 5.300 ;
        RECT 4.300 5.000 4.800 5.300 ;
        RECT 0.800 4.400 1.300 4.700 ;
        RECT 1.950 4.450 2.800 4.700 ;
        RECT 2.550 4.050 2.800 4.450 ;
        RECT 2.550 4.000 2.900 4.050 ;
        RECT 0.300 3.550 2.000 3.850 ;
        RECT 2.550 3.700 3.050 4.000 ;
        RECT 2.550 3.650 2.900 3.700 ;
        RECT 0.300 1.950 0.550 3.550 ;
        RECT 2.550 3.200 2.800 3.650 ;
        RECT 1.950 2.950 2.800 3.200 ;
        RECT 0.300 1.700 0.800 1.950 ;
        RECT 0.550 0.950 0.800 1.700 ;
        RECT 1.950 1.800 2.200 2.950 ;
        RECT 2.900 2.300 3.400 2.600 ;
        RECT 1.950 1.550 3.050 1.800 ;
        RECT 2.800 0.950 3.050 1.550 ;
        RECT 4.400 0.950 4.650 5.000 ;
      LAYER Via1 ;
        RECT 2.550 5.000 2.850 5.300 ;
        RECT 4.400 5.000 4.700 5.300 ;
        RECT 0.900 4.400 1.200 4.700 ;
        RECT 2.650 3.700 2.950 4.000 ;
        RECT 3.000 2.300 3.300 2.600 ;
      LAYER Metal2 ;
        RECT 2.450 5.300 2.950 5.350 ;
        RECT 4.300 5.300 4.800 5.350 ;
        RECT 2.450 5.000 4.800 5.300 ;
        RECT 2.450 4.950 2.950 5.000 ;
        RECT 4.300 4.950 4.800 5.000 ;
  END
END gf180mcu_osu_sc_gp12t3v3__tbuf_1


MACRO gf180mcu_osu_sc_gp12t3v3__clkinv_2
  CLASS BLOCK ;
  ORIGIN 0 0 ;
  FOREIGN gf180mcu_osu_sc_gp12t3v3__clkinv_2 ;
  SIZE 3.150 BY 8.400 ;
  PIN A
    ANTENNAGATEAREA 1.530000 ;
    PORT
      LAYER Metal2 ;
        RECT 0.450 3.650 0.950 4.050 ;
    END
  END A
  PIN Y
    ANTENNADIFFAREA 1.402500 ;
    PORT
      LAYER Metal2 ;
        RECT 1.500 5.050 2.000 5.450 ;
    END
  END Y
  PIN VDD
    ANTENNADIFFAREA 2.122500 ;
    PORT
      LAYER Nwell ;
        RECT 0.000 5.200 3.150 8.400 ;
      LAYER Metal1 ;
        RECT 0.000 7.800 3.150 8.400 ;
        RECT 0.550 5.750 0.800 7.800 ;
        RECT 2.300 5.750 2.550 7.800 ;
    END
  END VDD
  PIN VSS
    ANTENNADIFFAREA 1.187500 ;
    PORT
      LAYER Metal1 ;
        RECT 0.550 0.600 0.800 1.800 ;
        RECT 2.250 0.600 2.500 1.800 ;
        RECT 0.000 0.000 3.150 0.600 ;
    END
  END VSS
  OBS
      LAYER Metal1 ;
        RECT 1.400 5.500 1.650 7.450 ;
        RECT 1.400 5.400 1.850 5.500 ;
        RECT 1.400 5.100 2.000 5.400 ;
        RECT 1.400 4.950 1.850 5.100 ;
        RECT 0.450 3.700 0.950 4.000 ;
        RECT 1.400 0.950 1.650 4.950 ;
      LAYER Via1 ;
        RECT 1.600 5.100 1.900 5.400 ;
        RECT 0.550 3.700 0.850 4.000 ;
  END
END gf180mcu_osu_sc_gp12t3v3__clkinv_2


MACRO gf180mcu_osu_sc_gp12t3v3__clkbuf_2
  CLASS BLOCK ;
  ORIGIN 0 0 ;
  FOREIGN gf180mcu_osu_sc_gp12t3v3__clkbuf_2 ;
  SIZE 4.200 BY 8.400 ;
  PIN A
    ANTENNAGATEAREA 0.765000 ;
    PORT
      LAYER Metal2 ;
        RECT 0.850 4.700 1.250 4.750 ;
        RECT 0.800 4.400 1.300 4.700 ;
        RECT 0.850 4.350 1.250 4.400 ;
    END
  END A
  PIN Y
    ANTENNADIFFAREA 1.402500 ;
    PORT
      LAYER Metal2 ;
        RECT 2.200 5.050 2.700 5.450 ;
    END
  END Y
  PIN VDD
    ANTENNADIFFAREA 2.460000 ;
    PORT
      LAYER Nwell ;
        RECT 0.000 5.200 4.200 8.400 ;
      LAYER Metal1 ;
        RECT 0.000 7.800 4.200 8.400 ;
        RECT 1.400 5.750 1.650 7.800 ;
        RECT 3.100 5.750 3.350 7.800 ;
    END
  END VDD
  PIN VSS
    ANTENNADIFFAREA 1.567500 ;
    PORT
      LAYER Metal1 ;
        RECT 1.400 0.600 1.650 1.800 ;
        RECT 3.100 0.600 3.350 1.800 ;
        RECT 0.000 0.000 4.200 0.600 ;
    END
  END VSS
  OBS
      LAYER Metal1 ;
        RECT 0.550 6.100 0.800 7.450 ;
        RECT 0.300 5.750 0.800 6.100 ;
        RECT 0.300 3.650 0.550 5.750 ;
        RECT 2.250 5.450 2.500 7.450 ;
        RECT 2.250 5.400 2.550 5.450 ;
        RECT 2.200 5.100 2.700 5.400 ;
        RECT 2.250 5.050 2.550 5.100 ;
        RECT 0.800 4.400 1.300 4.700 ;
        RECT 0.300 3.400 0.800 3.650 ;
        RECT 0.550 3.100 2.000 3.400 ;
        RECT 0.550 0.950 0.800 3.100 ;
        RECT 2.250 0.950 2.500 5.050 ;
      LAYER Via1 ;
        RECT 2.300 5.100 2.600 5.400 ;
        RECT 0.900 4.400 1.200 4.700 ;
  END
END gf180mcu_osu_sc_gp12t3v3__clkbuf_2


MACRO gf180mcu_osu_sc_gp12t3v3__clkinv_16
  CLASS BLOCK ;
  ORIGIN 0 0 ;
  FOREIGN gf180mcu_osu_sc_gp12t3v3__clkinv_16 ;
  SIZE 15.050 BY 8.400 ;
  PIN A
    ANTENNAGATEAREA 12.240001 ;
    PORT
      LAYER Metal2 ;
        RECT 0.450 3.650 0.950 4.050 ;
    END
  END A
  PIN Y
    ANTENNADIFFAREA 11.220001 ;
    PORT
      LAYER Metal2 ;
        RECT 13.400 5.050 13.900 5.450 ;
    END
  END Y
  PIN VDD
    ANTENNADIFFAREA 12.295001 ;
    PORT
      LAYER Nwell ;
        RECT 0.000 5.200 15.050 8.400 ;
      LAYER Metal1 ;
        RECT 0.000 7.800 15.050 8.400 ;
        RECT 0.550 5.750 0.800 7.800 ;
        RECT 2.250 5.750 2.500 7.800 ;
        RECT 3.950 5.750 4.200 7.800 ;
        RECT 5.650 5.750 5.900 7.800 ;
        RECT 7.350 5.750 7.600 7.800 ;
        RECT 9.050 5.750 9.300 7.800 ;
        RECT 10.750 5.750 11.000 7.800 ;
        RECT 12.450 5.750 12.700 7.800 ;
        RECT 14.150 5.750 14.400 7.800 ;
    END
  END VDD
  PIN VSS
    ANTENNADIFFAREA 8.172501 ;
    PORT
      LAYER Metal1 ;
        RECT 0.550 0.600 0.800 1.800 ;
        RECT 2.250 0.600 2.500 1.800 ;
        RECT 3.950 0.600 4.200 1.800 ;
        RECT 5.650 0.600 5.900 1.800 ;
        RECT 7.350 0.600 7.600 1.800 ;
        RECT 9.050 0.600 9.300 1.800 ;
        RECT 10.750 0.600 11.000 1.800 ;
        RECT 12.450 0.600 12.700 1.800 ;
        RECT 14.150 0.600 14.400 1.800 ;
        RECT 0.000 0.000 15.050 0.600 ;
    END
  END VSS
  OBS
      LAYER Metal1 ;
        RECT 1.400 4.900 1.650 7.450 ;
        RECT 3.100 4.900 3.350 7.450 ;
        RECT 4.800 4.900 5.050 7.450 ;
        RECT 6.500 4.900 6.750 7.450 ;
        RECT 8.200 4.900 8.450 7.450 ;
        RECT 9.900 4.900 10.150 7.450 ;
        RECT 11.600 4.900 11.850 7.450 ;
        RECT 13.300 5.450 13.550 7.450 ;
        RECT 13.300 5.050 13.900 5.450 ;
        RECT 13.300 4.900 13.550 5.050 ;
        RECT 1.400 4.650 13.550 4.900 ;
        RECT 0.450 3.700 0.950 4.000 ;
        RECT 1.400 2.300 1.650 4.650 ;
        RECT 3.100 2.300 3.350 4.650 ;
        RECT 4.800 2.300 5.050 4.650 ;
        RECT 6.500 2.300 6.750 4.650 ;
        RECT 8.200 2.300 8.450 4.650 ;
        RECT 9.900 2.300 10.150 4.650 ;
        RECT 11.600 2.300 11.850 4.650 ;
        RECT 13.300 2.300 13.550 4.650 ;
        RECT 1.400 2.050 13.550 2.300 ;
        RECT 1.400 0.950 1.650 2.050 ;
        RECT 3.100 0.950 3.350 2.050 ;
        RECT 4.800 0.950 5.050 2.050 ;
        RECT 6.500 0.950 6.750 2.050 ;
        RECT 8.200 0.950 8.450 2.050 ;
        RECT 9.900 0.950 10.150 2.050 ;
        RECT 11.600 0.950 11.850 2.050 ;
        RECT 13.300 0.950 13.550 2.050 ;
      LAYER Via1 ;
        RECT 13.500 5.100 13.800 5.400 ;
        RECT 0.550 3.700 0.850 4.000 ;
  END
END gf180mcu_osu_sc_gp12t3v3__clkinv_16


MACRO gf180mcu_osu_sc_gp12t3v3__inv_2
  CLASS BLOCK ;
  ORIGIN 0 0 ;
  FOREIGN gf180mcu_osu_sc_gp12t3v3__inv_2 ;
  SIZE 3.150 BY 8.400 ;
  PIN A
    ANTENNAGATEAREA 1.530000 ;
    PORT
      LAYER Metal2 ;
        RECT 0.800 3.650 1.300 4.050 ;
    END
  END A
  PIN Y
    ANTENNADIFFAREA 1.402500 ;
    PORT
      LAYER Metal2 ;
        RECT 1.500 5.050 2.000 5.450 ;
    END
  END Y
  PIN VDD
    ANTENNADIFFAREA 2.460000 ;
    PORT
      LAYER Nwell ;
        RECT 0.000 5.200 3.150 8.400 ;
      LAYER Metal1 ;
        RECT 0.000 7.800 3.150 8.400 ;
        RECT 0.550 5.750 0.800 7.800 ;
        RECT 2.300 5.750 2.550 7.800 ;
    END
  END VDD
  PIN VSS
    ANTENNADIFFAREA 1.525000 ;
    PORT
      LAYER Metal1 ;
        RECT 0.550 0.600 0.800 1.800 ;
        RECT 2.250 0.600 2.500 1.800 ;
        RECT 0.000 0.000 3.150 0.600 ;
    END
  END VSS
  OBS
      LAYER Metal1 ;
        RECT 1.400 5.500 1.650 7.450 ;
        RECT 1.400 5.400 1.850 5.500 ;
        RECT 1.400 5.100 2.000 5.400 ;
        RECT 1.550 5.050 1.850 5.100 ;
        RECT 0.800 3.700 1.300 4.000 ;
        RECT 1.550 1.950 1.800 5.050 ;
        RECT 1.400 1.700 1.800 1.950 ;
        RECT 1.400 0.950 1.650 1.700 ;
      LAYER Via1 ;
        RECT 1.600 5.100 1.900 5.400 ;
        RECT 0.900 3.700 1.200 4.000 ;
  END
END gf180mcu_osu_sc_gp12t3v3__inv_2


MACRO gf180mcu_osu_sc_gp12t3v3__aoi22_1
  CLASS BLOCK ;
  ORIGIN 0 0 ;
  FOREIGN gf180mcu_osu_sc_gp12t3v3__aoi22_1 ;
  SIZE 5.250 BY 8.400 ;
  PIN A1
    ANTENNAGATEAREA 0.765000 ;
    PORT
      LAYER Metal2 ;
        RECT 1.500 4.350 2.000 4.750 ;
    END
  END A1
  PIN A0
    ANTENNAGATEAREA 0.765000 ;
    PORT
      LAYER Metal2 ;
        RECT 0.800 2.950 1.300 3.350 ;
    END
  END A0
  PIN B0
    ANTENNAGATEAREA 0.765000 ;
    PORT
      LAYER Metal2 ;
        RECT 2.550 3.650 3.050 4.050 ;
    END
  END B0
  PIN B1
    ANTENNAGATEAREA 0.765000 ;
    PORT
      LAYER Metal2 ;
        RECT 3.250 4.350 3.750 4.750 ;
    END
  END B1
  PIN Y
    ANTENNADIFFAREA 1.402500 ;
    PORT
      LAYER Metal2 ;
        RECT 3.000 6.700 3.500 6.750 ;
        RECT 4.350 6.700 4.850 6.750 ;
        RECT 3.000 6.400 4.850 6.700 ;
        RECT 3.000 6.350 3.500 6.400 ;
        RECT 4.350 6.350 4.850 6.400 ;
        RECT 4.300 5.050 4.800 5.450 ;
    END
  END Y
  PIN VDD
    ANTENNADIFFAREA 2.285000 ;
    PORT
      LAYER Nwell ;
        RECT 0.000 5.200 5.250 8.400 ;
      LAYER Metal1 ;
        RECT 0.000 7.800 5.250 8.400 ;
        RECT 1.400 6.500 1.650 7.800 ;
    END
  END VDD
  PIN VSS
    ANTENNADIFFAREA 2.200000 ;
    PORT
      LAYER Metal1 ;
        RECT 0.700 0.600 0.950 1.800 ;
        RECT 3.500 0.600 3.750 1.800 ;
        RECT 0.000 0.000 5.250 0.600 ;
    END
  END VSS
  OBS
      LAYER Metal1 ;
        RECT 0.550 6.150 0.800 7.450 ;
        RECT 2.250 6.150 2.500 7.450 ;
        RECT 3.100 6.700 3.350 7.450 ;
        RECT 3.000 6.400 3.500 6.700 ;
        RECT 3.950 6.150 4.200 7.450 ;
        RECT 0.550 5.900 4.200 6.150 ;
        RECT 4.450 6.300 4.750 6.800 ;
        RECT 4.450 5.400 4.700 6.300 ;
        RECT 4.300 5.100 4.800 5.400 ;
        RECT 1.500 4.400 2.000 4.700 ;
        RECT 3.250 4.400 3.750 4.700 ;
        RECT 2.550 3.700 3.050 4.000 ;
        RECT 4.400 3.450 4.650 5.100 ;
        RECT 0.800 3.000 1.300 3.300 ;
        RECT 2.100 3.200 4.650 3.450 ;
        RECT 2.100 0.950 2.350 3.200 ;
      LAYER Via1 ;
        RECT 3.100 6.400 3.400 6.700 ;
        RECT 4.450 6.400 4.750 6.700 ;
        RECT 4.400 5.100 4.700 5.400 ;
        RECT 1.600 4.400 1.900 4.700 ;
        RECT 3.350 4.400 3.650 4.700 ;
        RECT 2.650 3.700 2.950 4.000 ;
        RECT 0.900 3.000 1.200 3.300 ;
  END
END gf180mcu_osu_sc_gp12t3v3__aoi22_1


MACRO gf180mcu_osu_sc_gp12t3v3__tiel
  CLASS BLOCK ;
  ORIGIN 0 0 ;
  FOREIGN gf180mcu_osu_sc_gp12t3v3__tiel ;
  SIZE 2.450 BY 8.400 ;
  PIN Y
    ANTENNADIFFAREA 0.425000 ;
    PORT
      LAYER Metal2 ;
        RECT 1.500 2.250 2.000 2.650 ;
    END
  END Y
  PIN VDD
    ANTENNADIFFAREA 1.187500 ;
    PORT
      LAYER Nwell ;
        RECT 0.000 5.200 2.450 8.400 ;
      LAYER Metal1 ;
        RECT 0.000 7.800 2.450 8.400 ;
        RECT 0.550 5.750 0.800 7.800 ;
    END
  END VDD
  PIN VSS
    ANTENNADIFFAREA 0.762500 ;
    PORT
      LAYER Metal1 ;
        RECT 0.550 0.600 0.800 1.800 ;
        RECT 0.000 0.000 2.450 0.600 ;
    END
  END VSS
  OBS
      LAYER Metal1 ;
        RECT 1.400 5.300 1.650 7.450 ;
        RECT 1.150 5.050 1.650 5.300 ;
        RECT 1.600 2.600 1.850 2.650 ;
        RECT 1.400 2.300 2.000 2.600 ;
        RECT 1.400 2.250 1.850 2.300 ;
        RECT 1.400 0.950 1.650 2.250 ;
      LAYER Via1 ;
        RECT 1.600 2.300 1.900 2.600 ;
  END
END gf180mcu_osu_sc_gp12t3v3__tiel


MACRO gf180mcu_osu_sc_gp12t3v3__oai31_1
  CLASS BLOCK ;
  ORIGIN 0 0 ;
  FOREIGN gf180mcu_osu_sc_gp12t3v3__oai31_1 ;
  SIZE 4.900 BY 8.400 ;
  PIN A0
    ANTENNAGATEAREA 0.765000 ;
    PORT
      LAYER Metal2 ;
        RECT 0.800 2.250 1.300 2.650 ;
    END
  END A0
  PIN A1
    ANTENNAGATEAREA 0.765000 ;
    PORT
      LAYER Metal2 ;
        RECT 1.850 2.950 2.350 3.350 ;
    END
  END A1
  PIN A2
    ANTENNAGATEAREA 0.765000 ;
    PORT
      LAYER Metal2 ;
        RECT 2.550 4.350 3.050 4.750 ;
    END
  END A2
  PIN B
    ANTENNAGATEAREA 0.765000 ;
    PORT
      LAYER Metal2 ;
        RECT 3.250 2.950 3.750 3.350 ;
    END
  END B
  PIN Y
    ANTENNADIFFAREA 1.360000 ;
    PORT
      LAYER Metal2 ;
        RECT 3.950 5.050 4.450 5.450 ;
    END
  END Y
  PIN VDD
    ANTENNADIFFAREA 3.050000 ;
    PORT
      LAYER Nwell ;
        RECT 0.000 5.200 4.900 8.400 ;
      LAYER Metal1 ;
        RECT 0.000 7.800 4.900 8.400 ;
        RECT 1.050 5.750 1.300 7.800 ;
        RECT 3.850 5.750 4.100 7.800 ;
    END
  END VDD
  PIN VSS
    ANTENNADIFFAREA 2.242500 ;
    PORT
      LAYER Metal1 ;
        RECT 0.550 0.600 0.800 1.800 ;
        RECT 2.250 0.600 2.500 1.500 ;
        RECT 0.000 0.000 4.900 0.600 ;
    END
  END VSS
  OBS
      LAYER Metal1 ;
        RECT 3.000 5.300 3.250 7.450 ;
        RECT 4.000 5.400 4.450 5.450 ;
        RECT 3.950 5.300 4.450 5.400 ;
        RECT 3.000 5.000 4.450 5.300 ;
        RECT 2.550 4.400 3.050 4.700 ;
        RECT 1.850 3.000 2.350 3.300 ;
        RECT 3.250 3.000 3.750 3.300 ;
        RECT 0.800 2.300 1.300 2.600 ;
        RECT 4.200 2.500 4.450 5.000 ;
        RECT 3.950 2.250 4.450 2.500 ;
        RECT 1.400 1.750 3.350 2.000 ;
        RECT 1.400 0.950 1.650 1.750 ;
        RECT 3.100 0.950 3.350 1.750 ;
        RECT 3.950 0.950 4.200 2.250 ;
      LAYER Via1 ;
        RECT 4.050 5.100 4.350 5.400 ;
        RECT 2.650 4.400 2.950 4.700 ;
        RECT 1.950 3.000 2.250 3.300 ;
        RECT 3.350 3.000 3.650 3.300 ;
        RECT 0.900 2.300 1.200 2.600 ;
  END
END gf180mcu_osu_sc_gp12t3v3__oai31_1


MACRO gf180mcu_osu_sc_gp12t3v3__inv_1
  CLASS BLOCK ;
  ORIGIN 0 0 ;
  FOREIGN gf180mcu_osu_sc_gp12t3v3__inv_1 ;
  SIZE 2.450 BY 8.400 ;
  PIN A
    ANTENNAGATEAREA 0.765000 ;
    PORT
      LAYER Metal2 ;
        RECT 0.450 3.650 0.950 4.050 ;
    END
  END A
  PIN Y
    ANTENNADIFFAREA 1.275000 ;
    PORT
      LAYER Metal2 ;
        RECT 1.500 5.050 2.000 5.450 ;
    END
  END Y
  PIN VDD
    ANTENNADIFFAREA 1.187500 ;
    PORT
      LAYER Nwell ;
        RECT 0.000 5.200 2.450 8.400 ;
      LAYER Metal1 ;
        RECT 0.000 7.800 2.450 8.400 ;
        RECT 0.550 5.750 0.800 7.800 ;
    END
  END VDD
  PIN VSS
    ANTENNADIFFAREA 0.762500 ;
    PORT
      LAYER Metal1 ;
        RECT 0.550 0.600 0.800 1.800 ;
        RECT 0.000 0.000 2.450 0.600 ;
    END
  END VSS
  OBS
      LAYER Metal1 ;
        RECT 1.400 5.450 1.650 7.450 ;
        RECT 1.400 5.400 1.850 5.450 ;
        RECT 1.400 5.100 2.000 5.400 ;
        RECT 1.400 5.050 1.850 5.100 ;
        RECT 0.450 3.700 0.950 4.000 ;
        RECT 1.400 0.950 1.650 5.050 ;
      LAYER Via1 ;
        RECT 1.600 5.100 1.900 5.400 ;
        RECT 0.550 3.700 0.850 4.000 ;
  END
END gf180mcu_osu_sc_gp12t3v3__inv_1


MACRO gf180mcu_osu_sc_gp12t3v3__fill_4
  CLASS BLOCK ;
  ORIGIN 0 0 ;
  FOREIGN gf180mcu_osu_sc_gp12t3v3__fill_4 ;
  SIZE 1.400 BY 8.400 ;
  PIN VDD
    PORT
      LAYER Metal1 ;
        RECT 0.000 7.800 1.400 8.400 ;
    END
  END VDD
  PIN VSS
    PORT
      LAYER Metal1 ;
        RECT 0.000 0.000 1.400 0.600 ;
    END
  END VSS
  OBS
      LAYER Nwell ;
        RECT 0.000 5.200 1.400 8.400 ;
  END
END gf180mcu_osu_sc_gp12t3v3__fill_4


MACRO gf180mcu_osu_sc_gp12t3v3__aoi21_1
  CLASS BLOCK ;
  ORIGIN 0 0 ;
  FOREIGN gf180mcu_osu_sc_gp12t3v3__aoi21_1 ;
  SIZE 4.200 BY 8.400 ;
  PIN A0
    ANTENNAGATEAREA 0.765000 ;
    PORT
      LAYER Metal2 ;
        RECT 0.800 2.950 1.300 3.350 ;
    END
  END A0
  PIN A1
    ANTENNAGATEAREA 0.765000 ;
    PORT
      LAYER Metal2 ;
        RECT 1.500 4.350 2.000 4.750 ;
    END
  END A1
  PIN B
    ANTENNAGATEAREA 0.765000 ;
    PORT
      LAYER Metal2 ;
        RECT 2.550 3.650 3.050 4.050 ;
    END
  END B
  PIN Y
    ANTENNADIFFAREA 1.317500 ;
    PORT
      LAYER Metal2 ;
        RECT 2.900 5.050 3.400 5.450 ;
    END
  END Y
  PIN VDD
    ANTENNADIFFAREA 1.947500 ;
    PORT
      LAYER Nwell ;
        RECT 0.000 5.200 4.200 8.400 ;
      LAYER Metal1 ;
        RECT 0.000 7.800 4.200 8.400 ;
        RECT 1.400 6.500 1.650 7.800 ;
    END
  END VDD
  PIN VSS
    ANTENNADIFFAREA 1.862500 ;
    PORT
      LAYER Metal1 ;
        RECT 0.700 0.600 0.950 1.800 ;
        RECT 2.950 0.600 3.200 1.800 ;
        RECT 0.000 0.000 4.200 0.600 ;
    END
  END VSS
  OBS
      LAYER Metal1 ;
        RECT 0.550 6.250 0.800 7.450 ;
        RECT 2.250 6.250 2.500 7.450 ;
        RECT 0.550 6.000 2.500 6.250 ;
        RECT 3.100 5.450 3.350 7.450 ;
        RECT 3.000 5.400 3.350 5.450 ;
        RECT 2.900 5.100 3.400 5.400 ;
        RECT 3.000 5.050 3.350 5.100 ;
        RECT 1.500 4.400 2.000 4.700 ;
        RECT 3.100 4.500 3.350 5.050 ;
        RECT 3.100 4.250 3.550 4.500 ;
        RECT 2.550 3.700 3.050 4.000 ;
        RECT 0.800 3.000 1.300 3.300 ;
        RECT 3.300 2.800 3.550 4.250 ;
        RECT 2.100 2.550 3.550 2.800 ;
        RECT 2.100 0.950 2.350 2.550 ;
      LAYER Via1 ;
        RECT 3.000 5.100 3.300 5.400 ;
        RECT 1.600 4.400 1.900 4.700 ;
        RECT 2.650 3.700 2.950 4.000 ;
        RECT 0.900 3.000 1.200 3.300 ;
  END
END gf180mcu_osu_sc_gp12t3v3__aoi21_1


MACRO gf180mcu_osu_sc_gp12t3v3__dffsr_1
  CLASS BLOCK ;
  ORIGIN 0 0 ;
  FOREIGN gf180mcu_osu_sc_gp12t3v3__dffsr_1 ;
  SIZE 18.900 BY 8.400 ;
  PIN D
    ANTENNAGATEAREA 0.690000 ;
    PORT
      LAYER Metal2 ;
        RECT 5.700 3.650 6.200 4.050 ;
    END
  END D
  PIN CLK
    ANTENNAGATEAREA 2.295000 ;
    PORT
      LAYER Metal2 ;
        RECT 11.700 4.700 12.100 4.750 ;
        RECT 6.650 4.650 7.100 4.700 ;
        RECT 10.100 4.650 10.600 4.700 ;
        RECT 11.650 4.650 12.150 4.700 ;
        RECT 6.650 4.400 12.150 4.650 ;
        RECT 6.650 4.350 12.100 4.400 ;
        RECT 6.650 4.300 7.100 4.350 ;
        RECT 10.100 4.300 10.600 4.350 ;
    END
  END CLK
  PIN Q
    ANTENNADIFFAREA 1.275000 ;
    PORT
      LAYER Metal2 ;
        RECT 18.000 5.400 18.400 5.450 ;
        RECT 17.950 5.100 18.450 5.400 ;
        RECT 18.000 5.050 18.400 5.100 ;
    END
  END Q
  PIN QN
    ANTENNAGATEAREA 0.765000 ;
    ANTENNADIFFAREA 1.275000 ;
    PORT
      LAYER Metal2 ;
        RECT 17.300 4.700 17.700 4.750 ;
        RECT 17.250 4.400 17.750 4.700 ;
        RECT 17.300 4.350 17.700 4.400 ;
    END
  END QN
  PIN R
    ANTENNAGATEAREA 0.765000 ;
    PORT
      LAYER Metal2 ;
        RECT 0.450 3.650 0.950 4.050 ;
    END
  END R
  PIN VDD
    ANTENNADIFFAREA 11.437501 ;
    PORT
      LAYER Nwell ;
        RECT 0.000 5.200 18.900 8.400 ;
      LAYER Metal1 ;
        RECT 0.000 7.800 18.900 8.400 ;
        RECT 0.550 5.750 0.800 7.800 ;
        RECT 3.850 6.500 4.100 7.800 ;
        RECT 5.450 5.750 5.700 7.800 ;
        RECT 8.500 5.750 8.750 7.800 ;
        RECT 11.300 6.500 11.550 7.800 ;
        RECT 13.750 7.000 14.000 7.800 ;
        RECT 17.050 5.750 17.300 7.800 ;
    END
  END VDD
  PIN VSS
    ANTENNADIFFAREA 8.940001 ;
    PORT
      LAYER Metal1 ;
        RECT 0.550 0.600 0.800 1.800 ;
        RECT 2.300 0.600 2.550 1.800 ;
        RECT 4.550 0.600 4.800 1.800 ;
        RECT 5.450 0.600 5.700 1.800 ;
        RECT 8.500 0.600 8.750 1.400 ;
        RECT 11.300 0.600 11.550 1.800 ;
        RECT 13.050 0.600 13.300 1.800 ;
        RECT 15.300 0.600 15.550 1.800 ;
        RECT 17.050 0.600 17.300 1.800 ;
        RECT 0.000 0.000 18.900 0.600 ;
    END
  END VSS
  PIN S
    ANTENNAGATEAREA 1.530000 ;
    PORT
      LAYER Metal2 ;
        RECT 3.500 5.750 14.350 6.050 ;
        RECT 3.500 4.700 3.800 5.750 ;
        RECT 3.400 4.300 3.900 4.700 ;
        RECT 14.050 4.350 14.350 5.750 ;
        RECT 14.050 4.100 14.400 4.350 ;
        RECT 14.050 4.050 14.500 4.100 ;
        RECT 14.100 3.650 14.600 4.050 ;
    END
  END S
  OBS
      LAYER Metal1 ;
        RECT 0.450 3.700 0.950 4.000 ;
        RECT 1.400 2.500 1.650 7.450 ;
        RECT 2.150 2.750 2.400 7.450 ;
        RECT 3.000 6.250 3.250 7.450 ;
        RECT 4.700 6.250 4.950 7.450 ;
        RECT 3.000 6.000 4.950 6.250 ;
        RECT 7.100 5.400 7.350 7.450 ;
        RECT 9.900 6.500 10.150 7.450 ;
        RECT 5.150 5.150 7.350 5.400 ;
        RECT 9.000 6.250 10.150 6.500 ;
        RECT 3.400 4.350 3.900 4.650 ;
        RECT 5.150 3.800 5.400 5.150 ;
        RECT 8.100 5.000 8.600 5.300 ;
        RECT 6.650 4.350 7.650 4.650 ;
        RECT 6.750 4.300 7.050 4.350 ;
        RECT 2.650 3.500 3.150 3.800 ;
        RECT 4.400 3.500 5.400 3.800 ;
        RECT 5.700 3.700 6.200 4.000 ;
        RECT 2.150 2.500 3.400 2.750 ;
        RECT 4.500 2.500 4.750 2.550 ;
        RECT 5.150 2.500 5.400 3.500 ;
        RECT 1.300 2.200 1.800 2.500 ;
        RECT 3.150 2.200 4.900 2.500 ;
        RECT 5.150 2.250 6.450 2.500 ;
        RECT 7.350 2.350 7.650 4.350 ;
        RECT 8.200 2.500 8.500 5.000 ;
        RECT 9.000 3.700 9.250 6.250 ;
        RECT 10.100 5.350 10.400 5.450 ;
        RECT 10.000 5.050 10.500 5.350 ;
        RECT 10.100 4.650 10.400 5.050 ;
        RECT 10.750 5.000 11.250 5.300 ;
        RECT 12.150 5.200 12.400 7.450 ;
        RECT 12.900 6.750 13.150 7.450 ;
        RECT 14.600 6.750 14.850 7.450 ;
        RECT 12.900 6.500 14.850 6.750 ;
        RECT 13.050 5.300 13.350 5.400 ;
        RECT 15.450 5.300 15.700 7.450 ;
        RECT 8.950 3.450 9.250 3.700 ;
        RECT 9.550 4.350 10.600 4.650 ;
        RECT 1.400 2.150 1.700 2.200 ;
        RECT 1.400 0.950 1.650 2.150 ;
        RECT 3.150 0.950 3.400 2.200 ;
        RECT 4.500 2.150 4.750 2.200 ;
        RECT 6.050 1.800 6.450 2.250 ;
        RECT 7.250 2.050 7.750 2.350 ;
        RECT 8.100 2.200 8.600 2.500 ;
        RECT 8.950 1.850 9.200 3.450 ;
        RECT 9.550 2.450 9.850 4.350 ;
        RECT 10.850 3.800 11.150 5.000 ;
        RECT 12.150 4.950 12.700 5.200 ;
        RECT 11.650 4.400 12.150 4.700 ;
        RECT 12.450 3.800 12.700 4.950 ;
        RECT 13.050 5.000 15.850 5.300 ;
        RECT 13.050 4.900 13.350 5.000 ;
        RECT 10.800 3.500 11.300 3.800 ;
        RECT 12.150 3.550 12.700 3.800 ;
        RECT 14.100 3.700 14.600 4.000 ;
        RECT 10.100 2.850 10.600 3.150 ;
        RECT 12.150 2.750 12.450 3.550 ;
        RECT 15.450 3.150 15.700 5.000 ;
        RECT 16.200 4.650 16.450 7.450 ;
        RECT 17.900 5.450 18.150 7.450 ;
        RECT 17.900 5.100 18.450 5.450 ;
        RECT 17.900 5.050 18.400 5.100 ;
        RECT 17.900 4.950 18.300 5.050 ;
        RECT 17.250 4.650 17.750 4.700 ;
        RECT 16.200 4.400 17.750 4.650 ;
        RECT 16.200 4.350 17.650 4.400 ;
        RECT 17.300 4.300 17.650 4.350 ;
        RECT 14.450 2.850 16.900 3.150 ;
        RECT 9.450 2.150 9.950 2.450 ;
        RECT 6.050 1.550 7.350 1.800 ;
        RECT 8.950 1.600 10.300 1.850 ;
        RECT 7.100 0.950 7.350 1.550 ;
        RECT 9.900 1.550 10.300 1.600 ;
        RECT 9.900 0.950 10.150 1.550 ;
        RECT 12.150 0.950 12.400 2.750 ;
        RECT 12.950 2.150 13.450 2.450 ;
        RECT 14.450 0.950 14.700 2.850 ;
        RECT 14.950 2.150 15.450 2.450 ;
        RECT 17.300 2.300 17.550 4.300 ;
        RECT 18.000 3.950 18.300 4.950 ;
        RECT 16.200 2.050 17.550 2.300 ;
        RECT 17.900 3.700 18.300 3.950 ;
        RECT 16.200 0.950 16.450 2.050 ;
        RECT 17.900 0.950 18.150 3.700 ;
      LAYER Via1 ;
        RECT 0.550 3.700 0.850 4.000 ;
        RECT 3.500 4.350 3.800 4.650 ;
        RECT 6.750 4.350 7.050 4.650 ;
        RECT 2.750 3.500 3.050 3.800 ;
        RECT 4.500 3.500 4.800 3.800 ;
        RECT 5.800 3.700 6.100 4.000 ;
        RECT 1.400 2.200 1.700 2.500 ;
        RECT 4.500 2.200 4.800 2.500 ;
        RECT 10.850 5.000 11.150 5.300 ;
        RECT 10.200 4.350 10.500 4.650 ;
        RECT 8.200 2.200 8.500 2.500 ;
        RECT 11.750 4.400 12.050 4.700 ;
        RECT 15.450 5.000 15.750 5.300 ;
        RECT 10.900 3.500 11.200 3.800 ;
        RECT 14.200 3.700 14.500 4.000 ;
        RECT 18.050 5.100 18.350 5.400 ;
        RECT 17.350 4.400 17.650 4.700 ;
        RECT 10.200 2.850 10.500 3.150 ;
        RECT 12.150 2.850 12.450 3.150 ;
        RECT 16.500 2.850 16.800 3.150 ;
        RECT 13.050 2.150 13.350 2.450 ;
        RECT 15.050 2.150 15.350 2.450 ;
      LAYER Metal2 ;
        RECT 10.800 5.300 12.700 5.350 ;
        RECT 13.000 5.300 13.400 5.350 ;
        RECT 10.750 5.050 13.450 5.300 ;
        RECT 10.750 5.000 11.400 5.050 ;
        RECT 12.400 5.000 13.450 5.050 ;
        RECT 10.800 4.950 11.200 5.000 ;
        RECT 13.000 4.950 13.400 5.000 ;
        RECT 15.350 4.950 15.850 5.350 ;
        RECT 2.650 3.450 3.150 3.850 ;
        RECT 4.400 3.450 4.900 3.850 ;
        RECT 10.850 3.800 11.250 3.850 ;
        RECT 10.800 3.500 11.300 3.800 ;
        RECT 10.850 3.450 11.250 3.500 ;
        RECT 1.300 2.500 1.800 2.550 ;
        RECT 2.750 2.500 3.050 3.450 ;
        RECT 10.150 3.150 10.550 3.200 ;
        RECT 12.100 3.150 12.500 3.200 ;
        RECT 16.450 3.150 16.850 3.200 ;
        RECT 10.100 2.850 12.600 3.150 ;
        RECT 16.100 2.850 16.900 3.150 ;
        RECT 10.150 2.800 10.550 2.850 ;
        RECT 12.100 2.800 12.500 2.850 ;
        RECT 16.450 2.800 16.850 2.850 ;
        RECT 1.300 2.200 3.050 2.500 ;
        RECT 1.300 2.150 1.800 2.200 ;
        RECT 2.750 1.200 3.050 2.200 ;
        RECT 4.400 2.500 4.900 2.550 ;
        RECT 8.150 2.500 8.550 2.550 ;
        RECT 4.400 2.200 8.600 2.500 ;
        RECT 4.400 2.150 4.900 2.200 ;
        RECT 8.150 2.150 8.550 2.200 ;
        RECT 12.950 2.100 13.450 2.500 ;
        RECT 14.850 2.100 15.450 2.500 ;
        RECT 9.850 1.850 10.250 1.900 ;
        RECT 12.950 1.850 13.350 2.100 ;
        RECT 9.800 1.550 13.350 1.850 ;
        RECT 9.850 1.500 10.250 1.550 ;
        RECT 14.850 1.200 15.150 2.100 ;
        RECT 2.750 0.900 15.150 1.200 ;
  END
END gf180mcu_osu_sc_gp12t3v3__dffsr_1


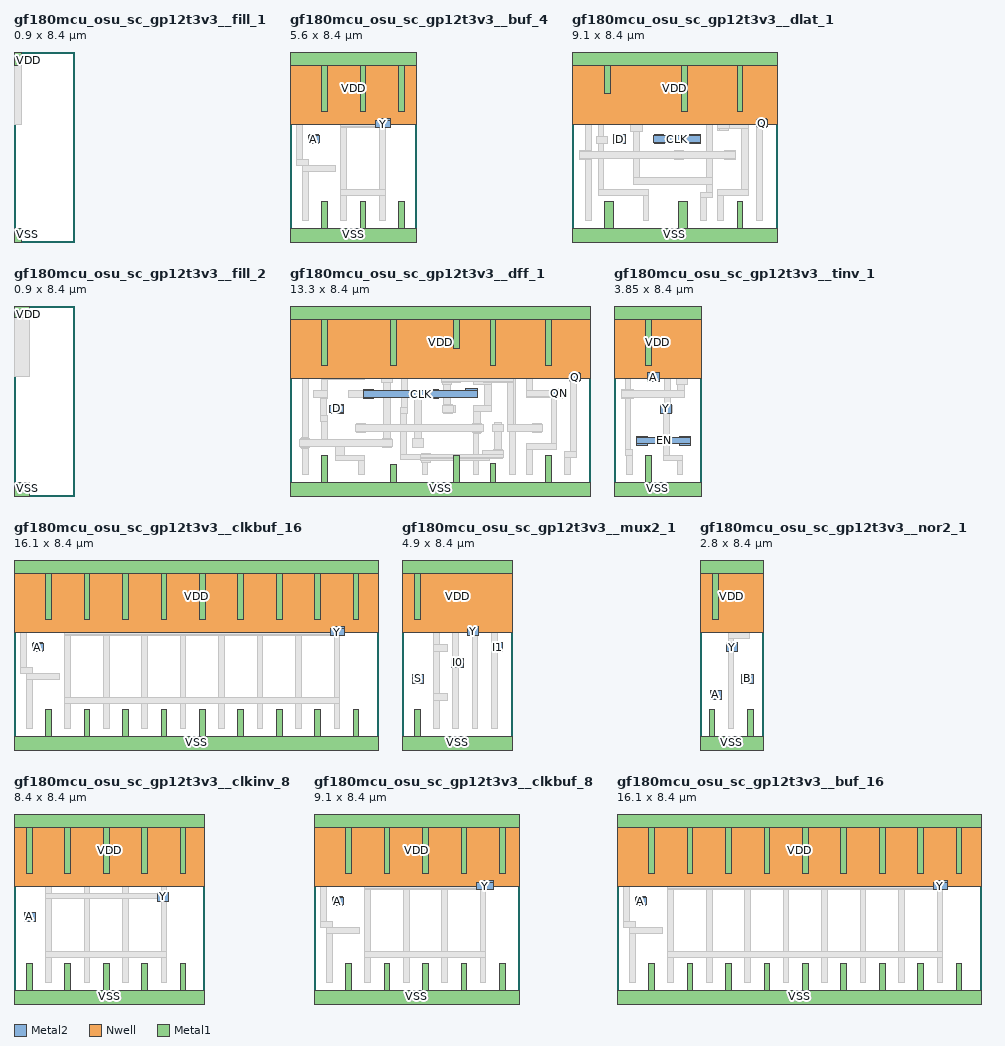
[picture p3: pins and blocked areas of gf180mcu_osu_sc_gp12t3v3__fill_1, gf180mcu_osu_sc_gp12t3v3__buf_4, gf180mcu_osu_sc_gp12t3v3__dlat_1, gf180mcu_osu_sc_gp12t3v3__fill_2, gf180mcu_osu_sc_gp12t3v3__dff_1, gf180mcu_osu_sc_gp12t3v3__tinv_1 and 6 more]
MACRO gf180mcu_osu_sc_gp12t3v3__fill_1
  CLASS BLOCK ;
  ORIGIN 0 0 ;
  FOREIGN gf180mcu_osu_sc_gp12t3v3__fill_1 ;
  SIZE 0.900 BY 8.400 ;
  PIN VDD
    PORT
      LAYER Metal1 ;
        RECT 0.000 7.800 0.350 8.400 ;
    END
  END VDD
  PIN VSS
    PORT
      LAYER Metal1 ;
        RECT 0.000 0.000 0.350 0.600 ;
    END
  END VSS
  OBS
      LAYER Nwell ;
        RECT 0.000 5.200 0.350 8.400 ;
  END
END gf180mcu_osu_sc_gp12t3v3__fill_1


MACRO gf180mcu_osu_sc_gp12t3v3__buf_4
  CLASS BLOCK ;
  ORIGIN 0 0 ;
  FOREIGN gf180mcu_osu_sc_gp12t3v3__buf_4 ;
  SIZE 5.600 BY 8.400 ;
  PIN A
    ANTENNAGATEAREA 0.765000 ;
    PORT
      LAYER Metal2 ;
        RECT 0.850 4.700 1.250 4.750 ;
        RECT 0.800 4.400 1.300 4.700 ;
        RECT 0.850 4.350 1.250 4.400 ;
    END
  END A
  PIN Y
    ANTENNADIFFAREA 2.805000 ;
    PORT
      LAYER Metal2 ;
        RECT 3.950 5.350 4.450 5.450 ;
        RECT 3.800 5.050 4.450 5.350 ;
    END
  END Y
  PIN VDD
    ANTENNADIFFAREA 4.070000 ;
    PORT
      LAYER Nwell ;
        RECT 0.000 5.200 5.600 8.400 ;
      LAYER Metal1 ;
        RECT 0.000 7.800 5.600 8.400 ;
        RECT 1.400 5.750 1.650 7.800 ;
        RECT 3.100 5.750 3.350 7.800 ;
        RECT 4.800 5.750 5.050 7.800 ;
    END
  END VDD
  PIN VSS
    ANTENNADIFFAREA 2.710000 ;
    PORT
      LAYER Metal1 ;
        RECT 1.400 0.600 1.650 1.800 ;
        RECT 3.100 0.600 3.350 1.800 ;
        RECT 4.800 0.600 5.050 1.800 ;
        RECT 0.000 0.000 5.600 0.600 ;
    END
  END VSS
  OBS
      LAYER Metal1 ;
        RECT 0.550 6.100 0.800 7.450 ;
        RECT 0.300 5.750 0.800 6.100 ;
        RECT 0.300 3.650 0.550 5.750 ;
        RECT 2.250 5.350 2.500 7.450 ;
        RECT 3.950 5.450 4.200 7.450 ;
        RECT 3.950 5.400 4.300 5.450 ;
        RECT 3.950 5.350 4.450 5.400 ;
        RECT 2.250 5.100 4.450 5.350 ;
        RECT 2.250 5.050 4.300 5.100 ;
        RECT 0.800 4.400 1.300 4.700 ;
        RECT 0.300 3.400 0.800 3.650 ;
        RECT 0.550 3.100 2.000 3.400 ;
        RECT 0.550 0.950 0.800 3.100 ;
        RECT 2.250 2.300 2.500 5.050 ;
        RECT 3.950 2.300 4.200 5.050 ;
        RECT 2.250 2.050 4.200 2.300 ;
        RECT 2.250 0.950 2.500 2.050 ;
        RECT 3.950 0.950 4.200 2.050 ;
      LAYER Via1 ;
        RECT 4.050 5.100 4.350 5.400 ;
        RECT 0.900 4.400 1.200 4.700 ;
  END
END gf180mcu_osu_sc_gp12t3v3__buf_4


MACRO gf180mcu_osu_sc_gp12t3v3__dlat_1
  CLASS BLOCK ;
  ORIGIN 0 0 ;
  FOREIGN gf180mcu_osu_sc_gp12t3v3__dlat_1 ;
  SIZE 9.100 BY 8.400 ;
  PIN D
    ANTENNAGATEAREA 0.765000 ;
    PORT
      LAYER Metal2 ;
        RECT 1.850 4.350 2.350 4.750 ;
    END
  END D
  PIN CLK
    ANTENNAGATEAREA 1.530000 ;
    PORT
      LAYER Metal2 ;
        RECT 3.650 4.700 4.050 4.750 ;
        RECT 5.200 4.700 5.700 4.750 ;
        RECT 3.600 4.400 5.700 4.700 ;
        RECT 3.650 4.350 4.100 4.400 ;
        RECT 5.200 4.350 5.700 4.400 ;
    END
  END CLK
  PIN Q
    ANTENNADIFFAREA 1.275000 ;
    PORT
      LAYER Metal2 ;
        RECT 8.200 5.400 8.600 5.450 ;
        RECT 8.150 5.100 8.650 5.400 ;
        RECT 8.200 5.050 8.600 5.100 ;
    END
  END Q
  PIN VDD
    ANTENNADIFFAREA 5.167500 ;
    PORT
      LAYER Nwell ;
        RECT 0.000 5.200 9.100 8.400 ;
      LAYER Metal1 ;
        RECT 0.000 7.800 9.100 8.400 ;
        RECT 1.450 6.550 1.700 7.800 ;
        RECT 4.850 5.750 5.100 7.800 ;
        RECT 7.300 5.750 7.550 7.800 ;
    END
  END VDD
  PIN VSS
    ANTENNADIFFAREA 4.020000 ;
    PORT
      LAYER Metal1 ;
        RECT 1.450 0.600 1.850 1.800 ;
        RECT 4.700 0.600 5.100 1.800 ;
        RECT 7.300 0.600 7.550 1.800 ;
        RECT 0.000 0.000 9.100 0.600 ;
    END
  END VSS
  OBS
      LAYER Metal1 ;
        RECT 0.600 4.050 0.850 7.450 ;
        RECT 3.150 6.000 3.400 7.450 ;
        RECT 1.150 5.750 3.400 6.000 ;
        RECT 5.700 5.800 5.950 7.450 ;
        RECT 1.150 4.650 1.400 5.750 ;
        RECT 5.700 5.450 6.200 5.800 ;
        RECT 2.600 4.900 3.100 5.200 ;
        RECT 1.100 4.350 1.550 4.650 ;
        RECT 1.850 4.400 2.350 4.700 ;
        RECT 0.500 4.000 0.850 4.050 ;
        RECT 0.350 3.700 0.850 4.000 ;
        RECT 0.450 3.650 0.850 3.700 ;
        RECT 0.600 0.950 0.850 3.650 ;
        RECT 1.150 2.300 1.400 4.350 ;
        RECT 2.700 2.850 3.000 4.900 ;
        RECT 3.600 4.400 4.100 4.700 ;
        RECT 5.200 4.400 5.700 4.700 ;
        RECT 4.500 3.700 5.000 4.000 ;
        RECT 5.950 2.850 6.200 5.450 ;
        RECT 6.450 5.500 6.700 7.450 ;
        RECT 6.450 5.300 6.850 5.500 ;
        RECT 8.150 5.450 8.400 7.450 ;
        RECT 8.150 5.400 8.550 5.450 ;
        RECT 6.450 5.250 6.950 5.300 ;
        RECT 6.450 5.000 7.800 5.250 ;
        RECT 6.450 4.950 6.850 5.000 ;
        RECT 6.750 3.700 7.250 4.000 ;
        RECT 2.700 2.550 6.200 2.850 ;
        RECT 1.150 2.050 3.400 2.300 ;
        RECT 5.950 2.200 6.200 2.550 ;
        RECT 7.500 2.300 7.800 5.000 ;
        RECT 3.150 0.950 3.400 2.050 ;
        RECT 5.700 1.950 6.200 2.200 ;
        RECT 6.450 2.050 7.800 2.300 ;
        RECT 8.150 5.100 8.650 5.400 ;
        RECT 8.150 5.050 8.550 5.100 ;
        RECT 5.700 0.950 5.950 1.950 ;
        RECT 6.450 0.950 6.700 2.050 ;
        RECT 8.150 0.950 8.400 5.050 ;
      LAYER Via1 ;
        RECT 1.950 4.400 2.250 4.700 ;
        RECT 0.450 3.700 0.750 4.000 ;
        RECT 3.700 4.400 4.000 4.700 ;
        RECT 5.300 4.400 5.600 4.700 ;
        RECT 4.600 3.700 4.900 4.000 ;
        RECT 6.550 5.000 6.850 5.300 ;
        RECT 6.850 3.700 7.150 4.000 ;
        RECT 8.250 5.100 8.550 5.400 ;
      LAYER Metal2 ;
        RECT 6.500 5.300 6.900 5.350 ;
        RECT 6.450 5.000 6.950 5.300 ;
        RECT 6.500 4.950 6.900 5.000 ;
        RECT 0.350 4.000 0.850 4.050 ;
        RECT 4.550 4.000 4.950 4.050 ;
        RECT 6.750 4.000 7.250 4.050 ;
        RECT 0.350 3.700 7.250 4.000 ;
        RECT 0.350 3.650 0.850 3.700 ;
        RECT 4.550 3.650 4.950 3.700 ;
        RECT 6.750 3.650 7.250 3.700 ;
  END
END gf180mcu_osu_sc_gp12t3v3__dlat_1


MACRO gf180mcu_osu_sc_gp12t3v3__fill_2
  CLASS BLOCK ;
  ORIGIN 0 0 ;
  FOREIGN gf180mcu_osu_sc_gp12t3v3__fill_2 ;
  SIZE 0.900 BY 8.400 ;
  PIN VDD
    PORT
      LAYER Metal1 ;
        RECT 0.000 7.900 0.700 8.400 ;
    END
  END VDD
  PIN VSS
    PORT
      LAYER Metal1 ;
        RECT 0.000 0.000 0.700 0.600 ;
    END
  END VSS
  OBS
      LAYER Nwell ;
        RECT 0.000 5.300 0.700 8.400 ;
  END
END gf180mcu_osu_sc_gp12t3v3__fill_2


MACRO gf180mcu_osu_sc_gp12t3v3__dff_1
  CLASS BLOCK ;
  ORIGIN 0 0 ;
  FOREIGN gf180mcu_osu_sc_gp12t3v3__dff_1 ;
  SIZE 13.300 BY 8.400 ;
  PIN D
    ANTENNAGATEAREA 0.765000 ;
    PORT
      LAYER Metal2 ;
        RECT 1.850 4.000 2.350 4.050 ;
        RECT 1.750 3.700 2.350 4.000 ;
        RECT 1.850 3.650 2.350 3.700 ;
    END
  END D
  PIN CLK
    ANTENNAGATEAREA 2.220000 ;
    PORT
      LAYER Metal2 ;
        RECT 3.250 4.650 3.700 4.700 ;
        RECT 6.050 4.650 6.550 4.700 ;
        RECT 7.750 4.650 8.300 4.750 ;
        RECT 3.250 4.350 8.300 4.650 ;
        RECT 3.250 4.300 3.700 4.350 ;
        RECT 6.050 4.300 6.550 4.350 ;
    END
  END CLK
  PIN Q
    ANTENNADIFFAREA 1.275000 ;
    PORT
      LAYER Metal2 ;
        RECT 12.400 5.400 12.800 5.450 ;
        RECT 12.350 5.100 12.850 5.400 ;
        RECT 12.400 5.050 12.800 5.100 ;
    END
  END Q
  PIN QN
    ANTENNAGATEAREA 0.765000 ;
    ANTENNADIFFAREA 1.275000 ;
    PORT
      LAYER Metal2 ;
        RECT 11.700 4.700 12.100 4.750 ;
        RECT 11.650 4.400 12.150 4.700 ;
        RECT 11.700 4.350 12.100 4.400 ;
    END
  END QN
  PIN VDD
    ANTENNADIFFAREA 7.965001 ;
    PORT
      LAYER Nwell ;
        RECT 0.000 5.200 13.300 8.400 ;
      LAYER Metal1 ;
        RECT 0.000 7.800 13.300 8.400 ;
        RECT 1.400 5.750 1.650 7.800 ;
        RECT 4.450 5.750 4.700 7.800 ;
        RECT 7.250 6.500 7.500 7.800 ;
        RECT 8.850 5.750 9.100 7.800 ;
        RECT 11.300 5.750 11.550 7.800 ;
    END
  END VDD
  PIN VSS
    ANTENNADIFFAREA 5.595000 ;
    PORT
      LAYER Metal1 ;
        RECT 1.400 0.600 1.650 1.800 ;
        RECT 4.450 0.600 4.700 1.400 ;
        RECT 7.250 0.600 7.500 1.800 ;
        RECT 8.850 0.600 9.100 1.450 ;
        RECT 11.300 0.600 11.550 1.800 ;
        RECT 0.000 0.000 13.300 0.600 ;
    END
  END VSS
  OBS
      LAYER Metal1 ;
        RECT 0.550 2.600 0.800 7.450 ;
        RECT 3.050 5.400 3.300 7.450 ;
        RECT 5.850 6.500 6.100 7.450 ;
        RECT 1.400 5.150 3.300 5.400 ;
        RECT 4.950 6.250 6.100 6.500 ;
        RECT 1.400 4.650 1.650 5.150 ;
        RECT 4.050 5.000 4.550 5.300 ;
        RECT 1.050 4.350 1.650 4.650 ;
        RECT 2.600 4.350 3.750 4.650 ;
        RECT 1.350 4.300 1.650 4.350 ;
        RECT 3.350 4.300 3.650 4.350 ;
        RECT 1.350 3.550 1.600 4.300 ;
        RECT 1.850 3.700 2.350 4.000 ;
        RECT 1.350 3.300 1.650 3.550 ;
        RECT 0.500 2.100 0.800 2.600 ;
        RECT 1.400 2.500 1.650 3.300 ;
        RECT 2.900 2.850 3.400 3.150 ;
        RECT 4.150 2.500 4.450 5.000 ;
        RECT 4.950 3.900 5.200 6.250 ;
        RECT 6.700 5.000 7.200 5.300 ;
        RECT 8.100 5.200 8.350 7.450 ;
        RECT 4.900 3.650 5.200 3.900 ;
        RECT 5.500 4.350 6.550 4.650 ;
        RECT 1.400 2.250 2.400 2.500 ;
        RECT 0.550 0.950 0.800 2.100 ;
        RECT 2.000 1.800 2.400 2.250 ;
        RECT 4.050 2.200 4.550 2.500 ;
        RECT 4.900 1.850 5.150 3.650 ;
        RECT 5.500 2.550 5.800 4.350 ;
        RECT 6.800 4.000 7.100 5.000 ;
        RECT 8.100 4.950 8.900 5.200 ;
        RECT 7.800 4.400 8.300 4.700 ;
        RECT 8.600 4.000 8.900 4.950 ;
        RECT 6.750 3.700 7.300 4.000 ;
        RECT 8.100 3.750 8.900 4.000 ;
        RECT 6.800 3.650 7.200 3.700 ;
        RECT 8.100 2.750 8.400 3.750 ;
        RECT 9.050 3.150 9.350 3.250 ;
        RECT 9.700 3.150 9.950 7.450 ;
        RECT 10.450 4.650 10.700 7.450 ;
        RECT 12.150 6.100 12.400 7.450 ;
        RECT 12.150 5.750 12.650 6.100 ;
        RECT 12.400 5.450 12.650 5.750 ;
        RECT 12.350 5.100 12.850 5.450 ;
        RECT 12.350 5.050 12.800 5.100 ;
        RECT 11.650 4.650 12.150 4.700 ;
        RECT 10.450 4.400 12.150 4.650 ;
        RECT 10.450 4.350 12.050 4.400 ;
        RECT 11.550 4.300 12.050 4.350 ;
        RECT 8.950 2.850 9.450 3.150 ;
        RECT 9.700 2.850 11.150 3.150 ;
        RECT 5.400 2.150 5.900 2.550 ;
        RECT 2.000 1.550 3.300 1.800 ;
        RECT 4.900 1.600 6.250 1.850 ;
        RECT 3.050 0.950 3.300 1.550 ;
        RECT 5.850 1.550 6.250 1.600 ;
        RECT 5.850 0.950 6.100 1.550 ;
        RECT 8.100 0.950 8.350 2.750 ;
        RECT 9.050 2.000 9.350 2.850 ;
        RECT 8.950 1.700 9.450 2.000 ;
        RECT 9.700 0.950 9.950 2.850 ;
        RECT 11.550 2.300 11.800 4.300 ;
        RECT 10.450 2.050 11.800 2.300 ;
        RECT 10.450 0.950 10.700 2.050 ;
        RECT 12.400 1.950 12.650 5.050 ;
        RECT 12.150 1.700 12.650 1.950 ;
        RECT 12.150 0.950 12.400 1.700 ;
      LAYER Via1 ;
        RECT 3.350 4.350 3.650 4.650 ;
        RECT 1.950 3.700 2.250 4.000 ;
        RECT 0.500 2.200 0.800 2.500 ;
        RECT 3.000 2.850 3.300 3.150 ;
        RECT 6.800 5.000 7.100 5.300 ;
        RECT 6.150 4.350 6.450 4.650 ;
        RECT 4.150 2.200 4.450 2.500 ;
        RECT 7.900 4.400 8.200 4.700 ;
        RECT 6.850 3.700 7.150 4.000 ;
        RECT 12.450 5.100 12.750 5.400 ;
        RECT 11.750 4.400 12.050 4.700 ;
        RECT 8.100 2.850 8.400 3.150 ;
        RECT 10.750 2.850 11.050 3.150 ;
        RECT 9.050 1.700 9.350 2.000 ;
      LAYER Metal2 ;
        RECT 6.750 5.300 8.850 5.350 ;
        RECT 6.700 5.050 9.900 5.300 ;
        RECT 6.700 5.000 7.550 5.050 ;
        RECT 8.550 5.000 9.900 5.050 ;
        RECT 6.750 4.950 7.150 5.000 ;
        RECT 6.800 4.000 7.200 4.050 ;
        RECT 6.750 3.700 7.250 4.000 ;
        RECT 6.800 3.650 7.200 3.700 ;
        RECT 2.950 3.150 3.350 3.200 ;
        RECT 8.050 3.150 8.450 3.200 ;
        RECT 9.600 3.150 9.900 5.000 ;
        RECT 10.700 3.150 11.100 3.200 ;
        RECT 2.900 2.850 8.550 3.150 ;
        RECT 9.600 2.850 11.150 3.150 ;
        RECT 2.950 2.800 3.350 2.850 ;
        RECT 8.050 2.800 8.450 2.850 ;
        RECT 10.700 2.800 11.100 2.850 ;
        RECT 0.450 2.500 0.850 2.550 ;
        RECT 4.100 2.500 4.500 2.550 ;
        RECT 0.400 2.200 4.550 2.500 ;
        RECT 0.450 2.150 0.850 2.200 ;
        RECT 4.100 2.150 4.500 2.200 ;
        RECT 9.000 2.000 9.400 2.050 ;
        RECT 5.800 1.850 6.200 1.900 ;
        RECT 8.500 1.850 9.450 2.000 ;
        RECT 5.750 1.700 9.450 1.850 ;
        RECT 5.750 1.650 9.400 1.700 ;
        RECT 5.750 1.550 8.800 1.650 ;
        RECT 5.800 1.500 6.200 1.550 ;
  END
END gf180mcu_osu_sc_gp12t3v3__dff_1


MACRO gf180mcu_osu_sc_gp12t3v3__tinv_1
  CLASS BLOCK ;
  ORIGIN 0 0 ;
  FOREIGN gf180mcu_osu_sc_gp12t3v3__tinv_1 ;
  SIZE 3.850 BY 8.400 ;
  PIN A
    ANTENNAGATEAREA 0.765000 ;
    PORT
      LAYER Metal2 ;
        RECT 1.500 5.050 2.000 5.450 ;
    END
  END A
  PIN EN
    ANTENNAGATEAREA 1.020000 ;
    PORT
      LAYER Metal2 ;
        RECT 1.000 2.600 1.500 2.650 ;
        RECT 2.900 2.600 3.400 2.650 ;
        RECT 1.000 2.300 3.400 2.600 ;
        RECT 1.000 2.250 1.500 2.300 ;
        RECT 2.900 2.250 3.400 2.300 ;
    END
  END EN
  PIN VDD
    ANTENNADIFFAREA 1.947500 ;
    PORT
      LAYER Nwell ;
        RECT 0.000 5.200 3.850 8.400 ;
      LAYER Metal1 ;
        RECT 0.000 7.800 3.850 8.400 ;
        RECT 1.400 5.750 1.650 7.800 ;
    END
  END VDD
  PIN VSS
    ANTENNADIFFAREA 1.480000 ;
    PORT
      LAYER Metal1 ;
        RECT 1.400 0.600 1.650 1.800 ;
        RECT 0.000 0.000 3.850 0.600 ;
    END
  END VSS
  PIN Y
    ANTENNADIFFAREA 1.275000 ;
    PORT
      LAYER Metal2 ;
        RECT 2.050 3.650 2.550 4.050 ;
    END
  END Y
  OBS
      LAYER Metal1 ;
        RECT 0.550 6.000 0.800 7.450 ;
        RECT 2.800 6.000 3.050 7.450 ;
        RECT 0.500 5.750 0.800 6.000 ;
        RECT 2.250 5.750 3.050 6.000 ;
        RECT 0.500 4.650 0.750 5.750 ;
        RECT 1.500 5.100 2.000 5.400 ;
        RECT 0.350 4.350 0.850 4.650 ;
        RECT 0.500 2.050 0.750 4.350 ;
        RECT 2.250 4.000 2.500 5.750 ;
        RECT 2.750 5.000 3.250 5.300 ;
        RECT 2.050 3.700 2.600 4.000 ;
        RECT 1.000 2.300 1.500 2.600 ;
        RECT 0.500 1.800 0.800 2.050 ;
        RECT 0.550 0.950 0.800 1.800 ;
        RECT 2.200 1.800 2.450 3.700 ;
        RECT 2.900 2.300 3.400 2.600 ;
        RECT 2.200 1.550 3.050 1.800 ;
        RECT 2.800 0.950 3.050 1.550 ;
      LAYER Via1 ;
        RECT 1.600 5.100 1.900 5.400 ;
        RECT 0.450 4.350 0.750 4.650 ;
        RECT 2.850 5.000 3.150 5.300 ;
        RECT 2.150 3.700 2.450 4.000 ;
        RECT 1.100 2.300 1.400 2.600 ;
        RECT 3.000 2.300 3.300 2.600 ;
      LAYER Metal2 ;
        RECT 2.750 4.950 3.250 5.350 ;
        RECT 0.350 4.650 0.850 4.700 ;
        RECT 2.800 4.650 3.100 4.950 ;
        RECT 0.350 4.350 3.100 4.650 ;
        RECT 0.350 4.300 0.850 4.350 ;
  END
END gf180mcu_osu_sc_gp12t3v3__tinv_1


MACRO gf180mcu_osu_sc_gp12t3v3__clkbuf_16
  CLASS BLOCK ;
  ORIGIN 0 0 ;
  FOREIGN gf180mcu_osu_sc_gp12t3v3__clkbuf_16 ;
  SIZE 16.100 BY 8.400 ;
  PIN A
    ANTENNAGATEAREA 0.765000 ;
    PORT
      LAYER Metal2 ;
        RECT 0.850 4.700 1.250 4.750 ;
        RECT 0.800 4.400 1.300 4.700 ;
        RECT 0.850 4.350 1.250 4.400 ;
    END
  END A
  PIN Y
    ANTENNADIFFAREA 11.220001 ;
    PORT
      LAYER Metal2 ;
        RECT 14.100 5.350 14.600 5.450 ;
        RECT 14.000 5.050 14.600 5.350 ;
    END
  END Y
  PIN VDD
    ANTENNADIFFAREA 12.380001 ;
    PORT
      LAYER Nwell ;
        RECT 0.000 5.200 16.100 8.400 ;
      LAYER Metal1 ;
        RECT 0.000 7.800 16.100 8.400 ;
        RECT 1.400 5.750 1.650 7.800 ;
        RECT 3.100 5.750 3.350 7.800 ;
        RECT 4.800 5.750 5.050 7.800 ;
        RECT 6.500 5.750 6.750 7.800 ;
        RECT 8.200 5.750 8.450 7.800 ;
        RECT 9.900 5.750 10.150 7.800 ;
        RECT 11.600 5.750 11.850 7.800 ;
        RECT 13.300 5.750 13.550 7.800 ;
        RECT 15.000 5.750 15.250 7.800 ;
    END
  END VDD
  PIN VSS
    ANTENNADIFFAREA 8.215000 ;
    PORT
      LAYER Metal1 ;
        RECT 1.400 0.600 1.650 1.800 ;
        RECT 3.100 0.600 3.350 1.800 ;
        RECT 4.800 0.600 5.050 1.800 ;
        RECT 6.500 0.600 6.750 1.800 ;
        RECT 8.200 0.600 8.450 1.800 ;
        RECT 9.900 0.600 10.150 1.800 ;
        RECT 11.600 0.600 11.850 1.800 ;
        RECT 13.300 0.600 13.550 1.800 ;
        RECT 15.000 0.600 15.250 1.800 ;
        RECT 0.000 0.000 16.100 0.600 ;
    END
  END VSS
  OBS
      LAYER Metal1 ;
        RECT 0.550 6.100 0.800 7.450 ;
        RECT 0.300 5.750 0.800 6.100 ;
        RECT 0.300 3.650 0.550 5.750 ;
        RECT 2.250 5.350 2.500 7.450 ;
        RECT 3.950 5.350 4.200 7.450 ;
        RECT 5.650 5.350 5.900 7.450 ;
        RECT 7.350 5.350 7.600 7.450 ;
        RECT 9.050 5.350 9.300 7.450 ;
        RECT 10.750 5.350 11.000 7.450 ;
        RECT 12.450 5.350 12.700 7.450 ;
        RECT 14.150 5.450 14.400 7.450 ;
        RECT 14.150 5.400 14.450 5.450 ;
        RECT 14.100 5.350 14.600 5.400 ;
        RECT 2.250 5.100 14.600 5.350 ;
        RECT 2.250 5.050 14.450 5.100 ;
        RECT 0.800 4.400 1.300 4.700 ;
        RECT 0.300 3.400 0.800 3.650 ;
        RECT 0.550 3.100 2.000 3.400 ;
        RECT 0.550 0.950 0.800 3.100 ;
        RECT 2.250 2.300 2.500 5.050 ;
        RECT 3.950 2.300 4.200 5.050 ;
        RECT 5.650 2.300 5.900 5.050 ;
        RECT 7.350 2.300 7.600 5.050 ;
        RECT 9.050 2.300 9.300 5.050 ;
        RECT 10.750 2.300 11.000 5.050 ;
        RECT 12.450 2.300 12.700 5.050 ;
        RECT 14.150 2.300 14.400 5.050 ;
        RECT 2.250 2.050 14.400 2.300 ;
        RECT 2.250 0.950 2.500 2.050 ;
        RECT 3.950 0.950 4.200 2.050 ;
        RECT 5.650 0.950 5.900 2.050 ;
        RECT 7.350 0.950 7.600 2.050 ;
        RECT 9.050 0.950 9.300 2.050 ;
        RECT 10.750 0.950 11.000 2.050 ;
        RECT 12.450 0.950 12.700 2.050 ;
        RECT 14.150 0.950 14.400 2.050 ;
      LAYER Via1 ;
        RECT 14.200 5.100 14.500 5.400 ;
        RECT 0.900 4.400 1.200 4.700 ;
  END
END gf180mcu_osu_sc_gp12t3v3__clkbuf_16


MACRO gf180mcu_osu_sc_gp12t3v3__mux2_1
  CLASS BLOCK ;
  ORIGIN 0 0 ;
  FOREIGN gf180mcu_osu_sc_gp12t3v3__mux2_1 ;
  SIZE 4.900 BY 8.400 ;
  PIN I0
    ANTENNADIFFAREA 1.275000 ;
    PORT
      LAYER Metal2 ;
        RECT 2.200 3.650 2.700 4.050 ;
    END
  END I0
  PIN I1
    ANTENNADIFFAREA 1.275000 ;
    PORT
      LAYER Metal2 ;
        RECT 3.950 4.350 4.450 4.750 ;
    END
  END I1
  PIN S
    ANTENNAGATEAREA 1.530000 ;
    PORT
      LAYER Metal2 ;
        RECT 0.450 2.950 0.950 3.350 ;
    END
  END S
  PIN Y
    ANTENNADIFFAREA 1.402500 ;
    PORT
      LAYER Metal2 ;
        RECT 2.900 5.050 3.400 5.450 ;
    END
  END Y
  PIN VDD
    ANTENNADIFFAREA 1.862500 ;
    PORT
      LAYER Nwell ;
        RECT 0.000 5.200 4.900 8.400 ;
      LAYER Metal1 ;
        RECT 0.000 7.800 4.900 8.400 ;
        RECT 0.550 5.750 0.800 7.800 ;
    END
  END VDD
  PIN VSS
    ANTENNADIFFAREA 1.437500 ;
    PORT
      LAYER Metal1 ;
        RECT 0.550 0.600 0.800 1.800 ;
        RECT 0.000 0.000 4.900 0.600 ;
    END
  END VSS
  OBS
      LAYER Metal1 ;
        RECT 1.400 4.650 1.650 7.450 ;
        RECT 1.400 4.350 2.000 4.650 ;
        RECT 0.450 3.000 0.950 3.300 ;
        RECT 1.400 2.500 1.650 4.350 ;
        RECT 2.250 4.050 2.500 7.450 ;
        RECT 3.100 5.450 3.350 7.450 ;
        RECT 2.900 5.050 3.400 5.450 ;
        RECT 2.200 3.650 2.700 4.050 ;
        RECT 1.400 2.200 2.000 2.500 ;
        RECT 1.400 0.950 1.650 2.200 ;
        RECT 2.250 0.950 2.500 3.650 ;
        RECT 3.100 0.950 3.350 5.050 ;
        RECT 3.950 4.750 4.200 7.450 ;
        RECT 3.950 4.350 4.450 4.750 ;
        RECT 3.950 0.950 4.200 4.350 ;
      LAYER Via1 ;
        RECT 0.550 3.000 0.850 3.300 ;
        RECT 3.000 5.100 3.300 5.400 ;
        RECT 2.300 3.700 2.600 4.000 ;
        RECT 4.050 4.400 4.350 4.700 ;
  END
END gf180mcu_osu_sc_gp12t3v3__mux2_1


MACRO gf180mcu_osu_sc_gp12t3v3__nor2_1
  CLASS BLOCK ;
  ORIGIN 0 0 ;
  FOREIGN gf180mcu_osu_sc_gp12t3v3__nor2_1 ;
  SIZE 2.800 BY 8.400 ;
  PIN A
    ANTENNAGATEAREA 0.765000 ;
    PORT
      LAYER Metal2 ;
        RECT 0.450 2.250 0.950 2.650 ;
    END
  END A
  PIN B
    ANTENNAGATEAREA 0.765000 ;
    PORT
      LAYER Metal2 ;
        RECT 1.850 2.950 2.350 3.350 ;
    END
  END B
  PIN Y
    ANTENNADIFFAREA 1.317500 ;
    PORT
      LAYER Metal2 ;
        RECT 1.150 4.350 1.650 4.750 ;
    END
  END Y
  PIN VDD
    ANTENNADIFFAREA 1.525000 ;
    PORT
      LAYER Nwell ;
        RECT 0.000 5.200 2.800 8.400 ;
      LAYER Metal1 ;
        RECT 0.000 7.800 2.800 8.400 ;
        RECT 0.550 5.750 0.800 7.800 ;
    END
  END VDD
  PIN VSS
    ANTENNADIFFAREA 1.525000 ;
    PORT
      LAYER Metal1 ;
        RECT 0.400 0.600 0.650 1.800 ;
        RECT 2.100 0.600 2.350 1.800 ;
        RECT 0.000 0.000 2.800 0.600 ;
    END
  END VSS
  OBS
      LAYER Metal1 ;
        RECT 1.950 5.200 2.200 7.450 ;
        RECT 1.250 4.950 2.200 5.200 ;
        RECT 1.250 4.700 1.500 4.950 ;
        RECT 1.150 4.400 1.650 4.700 ;
        RECT 0.450 2.300 0.950 2.600 ;
        RECT 1.250 0.950 1.500 4.400 ;
        RECT 1.850 3.000 2.350 3.300 ;
      LAYER Via1 ;
        RECT 1.250 4.400 1.550 4.700 ;
        RECT 0.550 2.300 0.850 2.600 ;
        RECT 1.950 3.000 2.250 3.300 ;
  END
END gf180mcu_osu_sc_gp12t3v3__nor2_1


MACRO gf180mcu_osu_sc_gp12t3v3__clkinv_8
  CLASS BLOCK ;
  ORIGIN 0 0 ;
  FOREIGN gf180mcu_osu_sc_gp12t3v3__clkinv_8 ;
  SIZE 8.400 BY 8.400 ;
  PIN A
    ANTENNAGATEAREA 6.120000 ;
    PORT
      LAYER Metal2 ;
        RECT 0.450 3.650 0.950 4.050 ;
    END
  END A
  PIN Y
    ANTENNADIFFAREA 5.610001 ;
    PORT
      LAYER Metal2 ;
        RECT 6.350 4.550 6.850 4.950 ;
    END
  END Y
  PIN VDD
    ANTENNADIFFAREA 6.530001 ;
    PORT
      LAYER Nwell ;
        RECT 0.000 5.200 8.400 8.400 ;
      LAYER Metal1 ;
        RECT 0.000 7.800 8.400 8.400 ;
        RECT 0.550 5.750 0.800 7.800 ;
        RECT 2.250 5.750 2.500 7.800 ;
        RECT 3.950 5.750 4.200 7.800 ;
        RECT 5.650 5.750 5.900 7.800 ;
        RECT 7.350 5.750 7.600 7.800 ;
    END
  END VDD
  PIN VSS
    ANTENNADIFFAREA 4.277500 ;
    PORT
      LAYER Metal1 ;
        RECT 0.550 0.600 0.800 1.800 ;
        RECT 2.250 0.600 2.500 1.800 ;
        RECT 3.950 0.600 4.200 1.800 ;
        RECT 5.650 0.600 5.900 1.800 ;
        RECT 7.350 0.600 7.600 1.800 ;
        RECT 0.000 0.000 8.400 0.600 ;
    END
  END VSS
  OBS
      LAYER Metal1 ;
        RECT 1.400 4.900 1.650 7.450 ;
        RECT 3.100 4.900 3.350 7.450 ;
        RECT 4.800 4.900 5.050 7.450 ;
        RECT 6.500 4.900 6.750 7.450 ;
        RECT 1.400 4.650 6.750 4.900 ;
        RECT 0.450 3.700 0.950 4.000 ;
        RECT 1.400 2.300 1.650 4.650 ;
        RECT 3.100 2.300 3.350 4.650 ;
        RECT 4.800 2.300 5.050 4.650 ;
        RECT 6.350 4.550 6.750 4.650 ;
        RECT 6.500 2.300 6.750 4.550 ;
        RECT 1.400 2.050 6.750 2.300 ;
        RECT 1.400 0.950 1.650 2.050 ;
        RECT 3.100 0.950 3.350 2.050 ;
        RECT 4.800 0.950 5.050 2.050 ;
        RECT 6.500 0.950 6.750 2.050 ;
      LAYER Via1 ;
        RECT 0.550 3.700 0.850 4.000 ;
        RECT 6.450 4.600 6.750 4.900 ;
  END
END gf180mcu_osu_sc_gp12t3v3__clkinv_8


MACRO gf180mcu_osu_sc_gp12t3v3__clkbuf_8
  CLASS BLOCK ;
  ORIGIN 0 0 ;
  FOREIGN gf180mcu_osu_sc_gp12t3v3__clkbuf_8 ;
  SIZE 9.100 BY 8.400 ;
  PIN A
    ANTENNAGATEAREA 0.765000 ;
    PORT
      LAYER Metal2 ;
        RECT 0.850 4.700 1.250 4.750 ;
        RECT 0.800 4.400 1.300 4.700 ;
        RECT 0.850 4.350 1.250 4.400 ;
    END
  END A
  PIN Y
    ANTENNADIFFAREA 5.610001 ;
    PORT
      LAYER Metal2 ;
        RECT 7.450 5.350 7.950 5.450 ;
        RECT 7.200 5.050 7.950 5.350 ;
    END
  END Y
  PIN VDD
    ANTENNADIFFAREA 6.615000 ;
    PORT
      LAYER Nwell ;
        RECT 0.000 5.200 9.100 8.400 ;
      LAYER Metal1 ;
        RECT 0.000 7.800 9.100 8.400 ;
        RECT 1.400 5.750 1.650 7.800 ;
        RECT 3.100 5.750 3.350 7.800 ;
        RECT 4.800 5.750 5.050 7.800 ;
        RECT 6.500 5.750 6.750 7.800 ;
        RECT 8.200 5.750 8.450 7.800 ;
    END
  END VDD
  PIN VSS
    ANTENNADIFFAREA 4.320000 ;
    PORT
      LAYER Metal1 ;
        RECT 1.400 0.600 1.650 1.800 ;
        RECT 3.100 0.600 3.350 1.800 ;
        RECT 4.800 0.600 5.050 1.800 ;
        RECT 6.500 0.600 6.750 1.800 ;
        RECT 8.200 0.600 8.450 1.800 ;
        RECT 0.000 0.000 9.100 0.600 ;
    END
  END VSS
  OBS
      LAYER Metal1 ;
        RECT 0.550 6.100 0.800 7.450 ;
        RECT 0.300 5.750 0.800 6.100 ;
        RECT 0.300 3.650 0.550 5.750 ;
        RECT 2.250 5.350 2.500 7.450 ;
        RECT 3.950 5.350 4.200 7.450 ;
        RECT 5.650 5.350 5.900 7.450 ;
        RECT 7.350 5.450 7.600 7.450 ;
        RECT 7.350 5.400 7.800 5.450 ;
        RECT 7.350 5.350 7.950 5.400 ;
        RECT 2.250 5.100 7.950 5.350 ;
        RECT 2.250 5.050 7.800 5.100 ;
        RECT 0.800 4.400 1.300 4.700 ;
        RECT 0.300 3.400 0.800 3.650 ;
        RECT 0.550 3.100 2.000 3.400 ;
        RECT 0.550 0.950 0.800 3.100 ;
        RECT 2.250 2.300 2.500 5.050 ;
        RECT 3.950 2.300 4.200 5.050 ;
        RECT 5.650 2.300 5.900 5.050 ;
        RECT 7.350 2.300 7.600 5.050 ;
        RECT 2.250 2.050 7.600 2.300 ;
        RECT 2.250 0.950 2.500 2.050 ;
        RECT 3.950 0.950 4.200 2.050 ;
        RECT 5.650 0.950 5.900 2.050 ;
        RECT 7.350 0.950 7.600 2.050 ;
      LAYER Via1 ;
        RECT 7.550 5.100 7.850 5.400 ;
        RECT 0.900 4.400 1.200 4.700 ;
  END
END gf180mcu_osu_sc_gp12t3v3__clkbuf_8


MACRO gf180mcu_osu_sc_gp12t3v3__buf_16
  CLASS BLOCK ;
  ORIGIN 0 0 ;
  FOREIGN gf180mcu_osu_sc_gp12t3v3__buf_16 ;
  SIZE 16.100 BY 8.400 ;
  PIN A
    ANTENNAGATEAREA 0.765000 ;
    PORT
      LAYER Metal2 ;
        RECT 0.850 4.700 1.250 4.750 ;
        RECT 0.800 4.400 1.300 4.700 ;
        RECT 0.850 4.350 1.250 4.400 ;
    END
  END A
  PIN Y
    ANTENNADIFFAREA 11.220001 ;
    PORT
      LAYER Metal2 ;
        RECT 14.100 5.350 14.600 5.450 ;
        RECT 14.000 5.050 14.600 5.350 ;
    END
  END Y
  PIN VDD
    ANTENNADIFFAREA 12.380001 ;
    PORT
      LAYER Nwell ;
        RECT 0.000 5.200 16.100 8.400 ;
      LAYER Metal1 ;
        RECT 0.000 7.800 16.100 8.400 ;
        RECT 1.400 5.750 1.650 7.800 ;
        RECT 3.100 5.750 3.350 7.800 ;
        RECT 4.800 5.750 5.050 7.800 ;
        RECT 6.500 5.750 6.750 7.800 ;
        RECT 8.200 5.750 8.450 7.800 ;
        RECT 9.900 5.750 10.150 7.800 ;
        RECT 11.600 5.750 11.850 7.800 ;
        RECT 13.300 5.750 13.550 7.800 ;
        RECT 15.000 5.750 15.250 7.800 ;
    END
  END VDD
  PIN VSS
    ANTENNADIFFAREA 8.215000 ;
    PORT
      LAYER Metal1 ;
        RECT 1.400 0.600 1.650 1.800 ;
        RECT 3.100 0.600 3.350 1.800 ;
        RECT 4.800 0.600 5.050 1.800 ;
        RECT 6.500 0.600 6.750 1.800 ;
        RECT 8.200 0.600 8.450 1.800 ;
        RECT 9.900 0.600 10.150 1.800 ;
        RECT 11.600 0.600 11.850 1.800 ;
        RECT 13.300 0.600 13.550 1.800 ;
        RECT 15.000 0.600 15.250 1.800 ;
        RECT 0.000 0.000 16.100 0.600 ;
    END
  END VSS
  OBS
      LAYER Metal1 ;
        RECT 0.550 6.100 0.800 7.450 ;
        RECT 0.300 5.750 0.800 6.100 ;
        RECT 0.300 3.650 0.550 5.750 ;
        RECT 2.250 5.350 2.500 7.450 ;
        RECT 3.950 5.350 4.200 7.450 ;
        RECT 5.650 5.350 5.900 7.450 ;
        RECT 7.350 5.350 7.600 7.450 ;
        RECT 9.050 5.350 9.300 7.450 ;
        RECT 10.750 5.350 11.000 7.450 ;
        RECT 12.450 5.350 12.700 7.450 ;
        RECT 14.150 5.450 14.400 7.450 ;
        RECT 14.100 5.400 14.450 5.450 ;
        RECT 14.100 5.350 14.600 5.400 ;
        RECT 2.250 5.100 14.600 5.350 ;
        RECT 2.250 5.050 14.450 5.100 ;
        RECT 0.800 4.400 1.300 4.700 ;
        RECT 0.300 3.400 0.800 3.650 ;
        RECT 0.550 3.100 2.000 3.400 ;
        RECT 0.550 0.950 0.800 3.100 ;
        RECT 2.250 2.300 2.500 5.050 ;
        RECT 3.950 2.300 4.200 5.050 ;
        RECT 5.650 2.300 5.900 5.050 ;
        RECT 7.350 2.300 7.600 5.050 ;
        RECT 9.050 2.300 9.300 5.050 ;
        RECT 10.750 2.300 11.000 5.050 ;
        RECT 12.450 2.300 12.700 5.050 ;
        RECT 14.150 2.300 14.400 5.050 ;
        RECT 2.250 2.050 14.400 2.300 ;
        RECT 2.250 0.950 2.500 2.050 ;
        RECT 3.950 0.950 4.200 2.050 ;
        RECT 5.650 0.950 5.900 2.050 ;
        RECT 7.350 0.950 7.600 2.050 ;
        RECT 9.050 0.950 9.300 2.050 ;
        RECT 10.750 0.950 11.000 2.050 ;
        RECT 12.450 0.950 12.700 2.050 ;
        RECT 14.150 0.950 14.400 2.050 ;
      LAYER Via1 ;
        RECT 14.200 5.100 14.500 5.400 ;
        RECT 0.900 4.400 1.200 4.700 ;
  END
END gf180mcu_osu_sc_gp12t3v3__buf_16


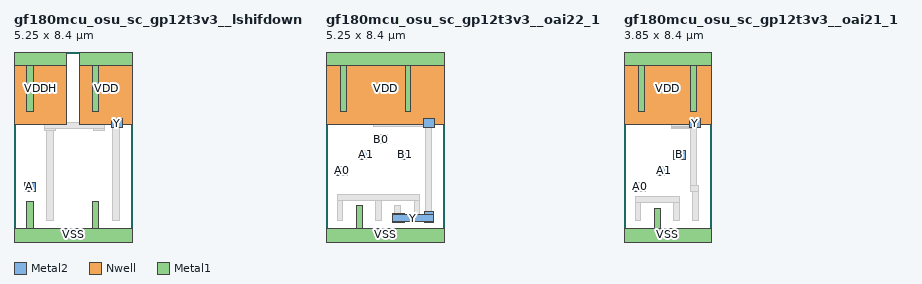
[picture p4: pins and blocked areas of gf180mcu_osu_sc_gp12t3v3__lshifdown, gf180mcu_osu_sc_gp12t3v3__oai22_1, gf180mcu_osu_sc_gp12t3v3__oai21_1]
MACRO gf180mcu_osu_sc_gp12t3v3__lshifdown
  CLASS BLOCK ;
  ORIGIN 0 0 ;
  FOREIGN gf180mcu_osu_sc_gp12t3v3__lshifdown ;
  SIZE 5.250 BY 8.400 ;
  PIN A
    ANTENNAGATEAREA 0.765000 ;
    PORT
      LAYER Metal2 ;
        RECT 0.450 2.250 0.950 2.650 ;
    END
  END A
  PIN Y
    ANTENNADIFFAREA 1.402500 ;
    PORT
      LAYER Metal2 ;
        RECT 4.300 5.050 4.800 5.450 ;
    END
  END Y
  PIN VDDH
    ANTENNADIFFAREA 1.272500 ;
    PORT
      LAYER Nwell ;
        RECT 0.000 5.200 2.300 8.400 ;
      LAYER Metal1 ;
        RECT 0.000 7.800 2.300 8.400 ;
        RECT 0.550 5.750 0.850 7.800 ;
    END
  END VDDH
  PIN VDD
    ANTENNADIFFAREA 1.272500 ;
    PORT
      LAYER Nwell ;
        RECT 2.900 5.200 5.250 8.400 ;
      LAYER Metal1 ;
        RECT 2.900 7.800 5.250 8.400 ;
        RECT 3.450 5.750 3.750 7.800 ;
    END
  END VDD
  PIN VSS
    ANTENNADIFFAREA 1.610000 ;
    PORT
      LAYER Metal1 ;
        RECT 0.550 0.600 0.850 1.800 ;
        RECT 3.450 0.600 3.750 1.800 ;
        RECT 0.000 0.000 5.250 0.600 ;
    END
  END VSS
  OBS
      LAYER Metal1 ;
        RECT 1.450 5.300 1.750 7.450 ;
        RECT 4.350 5.450 4.650 7.450 ;
        RECT 4.350 5.400 4.700 5.450 ;
        RECT 1.350 5.000 1.850 5.300 ;
        RECT 3.500 5.000 4.000 5.300 ;
        RECT 4.350 5.100 4.750 5.400 ;
        RECT 4.350 5.050 4.700 5.100 ;
        RECT 0.450 2.300 0.950 2.600 ;
        RECT 1.450 0.950 1.750 5.000 ;
        RECT 4.350 0.950 4.650 5.050 ;
      LAYER Via1 ;
        RECT 1.450 5.000 1.750 5.300 ;
        RECT 3.600 5.000 3.900 5.300 ;
        RECT 4.400 5.100 4.700 5.400 ;
        RECT 0.550 2.300 0.850 2.600 ;
      LAYER Metal2 ;
        RECT 1.350 5.300 1.850 5.350 ;
        RECT 3.500 5.300 4.000 5.350 ;
        RECT 1.350 5.000 4.000 5.300 ;
        RECT 1.350 4.950 1.850 5.000 ;
        RECT 3.500 4.950 4.000 5.000 ;
  END
END gf180mcu_osu_sc_gp12t3v3__lshifdown


MACRO gf180mcu_osu_sc_gp12t3v3__oai22_1
  CLASS BLOCK ;
  ORIGIN 0 0 ;
  FOREIGN gf180mcu_osu_sc_gp12t3v3__oai22_1 ;
  SIZE 5.250 BY 8.400 ;
  PIN A0
    ANTENNAGATEAREA 0.765000 ;
    PORT
      LAYER Metal2 ;
        RECT 0.450 2.950 0.950 3.350 ;
    END
  END A0
  PIN A1
    ANTENNAGATEAREA 0.765000 ;
    PORT
      LAYER Metal2 ;
        RECT 1.500 3.650 2.000 4.050 ;
    END
  END A1
  PIN B0
    ANTENNAGATEAREA 0.765000 ;
    PORT
      LAYER Metal2 ;
        RECT 2.200 4.350 2.700 4.750 ;
    END
  END B0
  PIN B1
    ANTENNAGATEAREA 0.765000 ;
    PORT
      LAYER Metal2 ;
        RECT 3.250 3.650 3.750 4.050 ;
    END
  END B1
  PIN Y
    ANTENNADIFFAREA 1.402500 ;
    PORT
      LAYER Metal2 ;
        RECT 4.300 5.050 4.800 5.450 ;
        RECT 2.950 1.200 3.450 1.250 ;
        RECT 4.350 1.200 4.750 1.350 ;
        RECT 2.950 0.900 4.750 1.200 ;
        RECT 2.950 0.850 3.450 0.900 ;
        RECT 4.350 0.850 4.750 0.900 ;
    END
  END Y
  PIN VDD
    ANTENNADIFFAREA 3.050000 ;
    PORT
      LAYER Nwell ;
        RECT 0.000 5.200 5.250 8.400 ;
      LAYER Metal1 ;
        RECT 0.000 7.800 5.250 8.400 ;
        RECT 0.650 5.750 0.900 7.800 ;
        RECT 3.500 5.750 3.750 7.800 ;
    END
  END VDD
  PIN VSS
    ANTENNADIFFAREA 1.817500 ;
    PORT
      LAYER Metal1 ;
        RECT 1.350 0.600 1.600 1.600 ;
        RECT 0.000 0.000 5.250 0.600 ;
    END
  END VSS
  OBS
      LAYER Metal1 ;
        RECT 2.100 5.400 2.350 7.450 ;
        RECT 4.400 5.400 4.650 5.450 ;
        RECT 2.100 5.100 4.800 5.400 ;
        RECT 2.200 4.400 2.700 4.700 ;
        RECT 1.500 3.700 2.000 4.000 ;
        RECT 3.250 3.700 3.750 4.000 ;
        RECT 0.450 3.000 0.950 3.300 ;
        RECT 0.500 1.850 4.150 2.100 ;
        RECT 0.500 0.950 0.750 1.850 ;
        RECT 2.200 0.950 2.450 1.850 ;
        RECT 3.050 1.200 3.300 1.600 ;
        RECT 2.950 0.900 3.450 1.200 ;
        RECT 3.900 0.950 4.150 1.850 ;
        RECT 4.400 1.350 4.650 5.100 ;
        RECT 4.400 0.850 4.700 1.350 ;
      LAYER Via1 ;
        RECT 4.400 5.100 4.700 5.400 ;
        RECT 2.300 4.400 2.600 4.700 ;
        RECT 1.600 3.700 1.900 4.000 ;
        RECT 3.350 3.700 3.650 4.000 ;
        RECT 0.550 3.000 0.850 3.300 ;
        RECT 3.050 0.900 3.350 1.200 ;
        RECT 4.400 0.950 4.700 1.250 ;
  END
END gf180mcu_osu_sc_gp12t3v3__oai22_1


MACRO gf180mcu_osu_sc_gp12t3v3__oai21_1
  CLASS BLOCK ;
  ORIGIN 0 0 ;
  FOREIGN gf180mcu_osu_sc_gp12t3v3__oai21_1 ;
  SIZE 3.850 BY 8.400 ;
  PIN A0
    ANTENNAGATEAREA 0.765000 ;
    PORT
      LAYER Metal2 ;
        RECT 0.450 2.250 0.950 2.650 ;
    END
  END A0
  PIN A1
    ANTENNAGATEAREA 0.765000 ;
    PORT
      LAYER Metal2 ;
        RECT 1.500 2.950 2.000 3.350 ;
    END
  END A1
  PIN B
    ANTENNAGATEAREA 0.765000 ;
    PORT
      LAYER Metal2 ;
        RECT 2.200 3.650 2.700 4.050 ;
    END
  END B
  PIN Y
    ANTENNADIFFAREA 1.360000 ;
    PORT
      LAYER Metal2 ;
        RECT 2.900 5.050 3.400 5.450 ;
    END
  END Y
  PIN VDD
    ANTENNADIFFAREA 2.712500 ;
    PORT
      LAYER Nwell ;
        RECT 0.000 5.200 3.850 8.400 ;
      LAYER Metal1 ;
        RECT 0.000 7.800 3.850 8.400 ;
        RECT 0.650 5.750 0.900 7.800 ;
        RECT 2.950 5.750 3.200 7.800 ;
    END
  END VDD
  PIN VSS
    ANTENNADIFFAREA 1.480000 ;
    PORT
      LAYER Metal1 ;
        RECT 1.350 0.600 1.600 1.500 ;
        RECT 0.000 0.000 3.850 0.600 ;
    END
  END VSS
  OBS
      LAYER Metal1 ;
        RECT 2.100 5.300 2.350 7.450 ;
        RECT 2.900 5.300 3.400 5.400 ;
        RECT 2.100 5.100 3.400 5.300 ;
        RECT 2.100 5.050 3.250 5.100 ;
        RECT 2.100 5.000 3.200 5.050 ;
        RECT 2.200 3.700 2.700 4.000 ;
        RECT 1.500 3.000 2.000 3.300 ;
        RECT 0.450 2.300 0.950 2.600 ;
        RECT 2.950 2.500 3.200 5.000 ;
        RECT 2.950 2.250 3.300 2.500 ;
        RECT 0.500 1.750 2.450 2.000 ;
        RECT 0.500 0.950 0.750 1.750 ;
        RECT 2.200 0.950 2.450 1.750 ;
        RECT 3.050 0.950 3.300 2.250 ;
      LAYER Via1 ;
        RECT 3.000 5.100 3.300 5.400 ;
        RECT 2.300 3.700 2.600 4.000 ;
        RECT 1.600 3.000 1.900 3.300 ;
        RECT 0.550 2.300 0.850 2.600 ;
  END
END gf180mcu_osu_sc_gp12t3v3__oai21_1


END LIBRARY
